##
## LEF for PtnCells ;
## created by Innovus v15.23-s045_1 on Sun Mar 23 12:35:52 2025
##

VERSION 5.8 ;

BUSBITCHARS "[]" ;
DIVIDERCHAR "/" ;

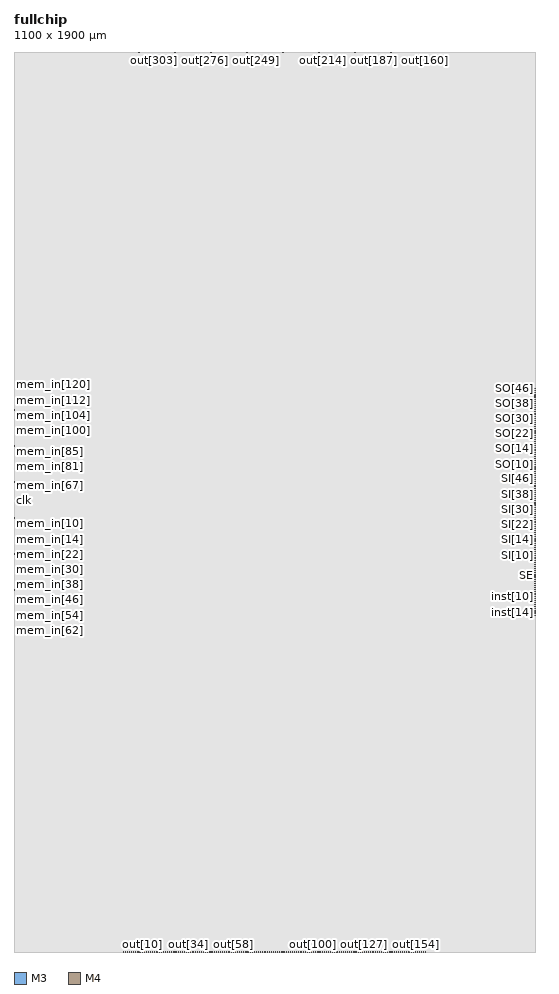
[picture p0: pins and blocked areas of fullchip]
MACRO fullchip
  CLASS BLOCK ;
  SIZE 1100.0000 BY 1900.0000 ;
  FOREIGN fullchip 0.0000 0.0000 ;
  ORIGIN 0 0 ;
  SYMMETRY X Y R90 ;
  PIN clk
    DIRECTION INPUT ;
    USE SIGNAL ;
    PORT
      LAYER M3 ;
        RECT 0.0000 952.1500 0.5200 952.2500 ;
    END
  END clk
  PIN mem_in[127]
    DIRECTION INPUT ;
    USE SIGNAL ;
    PORT
      LAYER M3 ;
        RECT 0.0000 1208.1500 0.5200 1208.2500 ;
    END
  END mem_in[127]
  PIN mem_in[126]
    DIRECTION INPUT ;
    USE SIGNAL ;
    PORT
      LAYER M3 ;
        RECT 0.0000 1204.1500 0.5200 1204.2500 ;
    END
  END mem_in[126]
  PIN mem_in[125]
    DIRECTION INPUT ;
    USE SIGNAL ;
    PORT
      LAYER M3 ;
        RECT 0.0000 1200.1500 0.5200 1200.2500 ;
    END
  END mem_in[125]
  PIN mem_in[124]
    DIRECTION INPUT ;
    USE SIGNAL ;
    PORT
      LAYER M3 ;
        RECT 0.0000 1196.1500 0.5200 1196.2500 ;
    END
  END mem_in[124]
  PIN mem_in[123]
    DIRECTION INPUT ;
    USE SIGNAL ;
    PORT
      LAYER M3 ;
        RECT 0.0000 1192.1500 0.5200 1192.2500 ;
    END
  END mem_in[123]
  PIN mem_in[122]
    DIRECTION INPUT ;
    USE SIGNAL ;
    PORT
      LAYER M3 ;
        RECT 0.0000 1188.1500 0.5200 1188.2500 ;
    END
  END mem_in[122]
  PIN mem_in[121]
    DIRECTION INPUT ;
    USE SIGNAL ;
    PORT
      LAYER M3 ;
        RECT 0.0000 1184.1500 0.5200 1184.2500 ;
    END
  END mem_in[121]
  PIN mem_in[120]
    DIRECTION INPUT ;
    USE SIGNAL ;
    PORT
      LAYER M3 ;
        RECT 0.0000 1180.1500 0.5200 1180.2500 ;
    END
  END mem_in[120]
  PIN mem_in[119]
    DIRECTION INPUT ;
    USE SIGNAL ;
    PORT
      LAYER M3 ;
        RECT 0.0000 1176.1500 0.5200 1176.2500 ;
    END
  END mem_in[119]
  PIN mem_in[118]
    DIRECTION INPUT ;
    USE SIGNAL ;
    PORT
      LAYER M3 ;
        RECT 0.0000 1172.1500 0.5200 1172.2500 ;
    END
  END mem_in[118]
  PIN mem_in[117]
    DIRECTION INPUT ;
    USE SIGNAL ;
    PORT
      LAYER M3 ;
        RECT 0.0000 1168.1500 0.5200 1168.2500 ;
    END
  END mem_in[117]
  PIN mem_in[116]
    DIRECTION INPUT ;
    USE SIGNAL ;
    PORT
      LAYER M3 ;
        RECT 0.0000 1164.1500 0.5200 1164.2500 ;
    END
  END mem_in[116]
  PIN mem_in[115]
    DIRECTION INPUT ;
    USE SIGNAL ;
    PORT
      LAYER M3 ;
        RECT 0.0000 1160.1500 0.5200 1160.2500 ;
    END
  END mem_in[115]
  PIN mem_in[114]
    DIRECTION INPUT ;
    USE SIGNAL ;
    PORT
      LAYER M3 ;
        RECT 0.0000 1156.1500 0.5200 1156.2500 ;
    END
  END mem_in[114]
  PIN mem_in[113]
    DIRECTION INPUT ;
    USE SIGNAL ;
    PORT
      LAYER M3 ;
        RECT 0.0000 1152.1500 0.5200 1152.2500 ;
    END
  END mem_in[113]
  PIN mem_in[112]
    DIRECTION INPUT ;
    USE SIGNAL ;
    PORT
      LAYER M3 ;
        RECT 0.0000 1148.1500 0.5200 1148.2500 ;
    END
  END mem_in[112]
  PIN mem_in[111]
    DIRECTION INPUT ;
    USE SIGNAL ;
    PORT
      LAYER M3 ;
        RECT 0.0000 1144.1500 0.5200 1144.2500 ;
    END
  END mem_in[111]
  PIN mem_in[110]
    DIRECTION INPUT ;
    USE SIGNAL ;
    PORT
      LAYER M3 ;
        RECT 0.0000 1140.1500 0.5200 1140.2500 ;
    END
  END mem_in[110]
  PIN mem_in[109]
    DIRECTION INPUT ;
    USE SIGNAL ;
    PORT
      LAYER M3 ;
        RECT 0.0000 1136.1500 0.5200 1136.2500 ;
    END
  END mem_in[109]
  PIN mem_in[108]
    DIRECTION INPUT ;
    USE SIGNAL ;
    PORT
      LAYER M3 ;
        RECT 0.0000 1132.1500 0.5200 1132.2500 ;
    END
  END mem_in[108]
  PIN mem_in[107]
    DIRECTION INPUT ;
    USE SIGNAL ;
    PORT
      LAYER M3 ;
        RECT 0.0000 1128.1500 0.5200 1128.2500 ;
    END
  END mem_in[107]
  PIN mem_in[106]
    DIRECTION INPUT ;
    USE SIGNAL ;
    PORT
      LAYER M3 ;
        RECT 0.0000 1124.1500 0.5200 1124.2500 ;
    END
  END mem_in[106]
  PIN mem_in[105]
    DIRECTION INPUT ;
    USE SIGNAL ;
    PORT
      LAYER M3 ;
        RECT 0.0000 1120.1500 0.5200 1120.2500 ;
    END
  END mem_in[105]
  PIN mem_in[104]
    DIRECTION INPUT ;
    USE SIGNAL ;
    PORT
      LAYER M3 ;
        RECT 0.0000 1116.1500 0.5200 1116.2500 ;
    END
  END mem_in[104]
  PIN mem_in[103]
    DIRECTION INPUT ;
    USE SIGNAL ;
    PORT
      LAYER M3 ;
        RECT 0.0000 1112.1500 0.5200 1112.2500 ;
    END
  END mem_in[103]
  PIN mem_in[102]
    DIRECTION INPUT ;
    USE SIGNAL ;
    PORT
      LAYER M3 ;
        RECT 0.0000 1108.1500 0.5200 1108.2500 ;
    END
  END mem_in[102]
  PIN mem_in[101]
    DIRECTION INPUT ;
    USE SIGNAL ;
    PORT
      LAYER M3 ;
        RECT 0.0000 1104.1500 0.5200 1104.2500 ;
    END
  END mem_in[101]
  PIN mem_in[100]
    DIRECTION INPUT ;
    USE SIGNAL ;
    PORT
      LAYER M3 ;
        RECT 0.0000 1100.1500 0.5200 1100.2500 ;
    END
  END mem_in[100]
  PIN mem_in[99]
    DIRECTION INPUT ;
    USE SIGNAL ;
    PORT
      LAYER M3 ;
        RECT 0.0000 1096.1500 0.5200 1096.2500 ;
    END
  END mem_in[99]
  PIN mem_in[98]
    DIRECTION INPUT ;
    USE SIGNAL ;
    PORT
      LAYER M3 ;
        RECT 0.0000 1092.1500 0.5200 1092.2500 ;
    END
  END mem_in[98]
  PIN mem_in[97]
    DIRECTION INPUT ;
    USE SIGNAL ;
    PORT
      LAYER M3 ;
        RECT 0.0000 1088.1500 0.5200 1088.2500 ;
    END
  END mem_in[97]
  PIN mem_in[96]
    DIRECTION INPUT ;
    USE SIGNAL ;
    PORT
      LAYER M3 ;
        RECT 0.0000 1084.1500 0.5200 1084.2500 ;
    END
  END mem_in[96]
  PIN mem_in[95]
    DIRECTION INPUT ;
    USE SIGNAL ;
    PORT
      LAYER M3 ;
        RECT 0.0000 1080.1500 0.5200 1080.2500 ;
    END
  END mem_in[95]
  PIN mem_in[94]
    DIRECTION INPUT ;
    USE SIGNAL ;
    PORT
      LAYER M3 ;
        RECT 0.0000 1076.1500 0.5200 1076.2500 ;
    END
  END mem_in[94]
  PIN mem_in[93]
    DIRECTION INPUT ;
    USE SIGNAL ;
    PORT
      LAYER M3 ;
        RECT 0.0000 1072.1500 0.5200 1072.2500 ;
    END
  END mem_in[93]
  PIN mem_in[92]
    DIRECTION INPUT ;
    USE SIGNAL ;
    PORT
      LAYER M3 ;
        RECT 0.0000 1068.1500 0.5200 1068.2500 ;
    END
  END mem_in[92]
  PIN mem_in[91]
    DIRECTION INPUT ;
    USE SIGNAL ;
    PORT
      LAYER M3 ;
        RECT 0.0000 1064.1500 0.5200 1064.2500 ;
    END
  END mem_in[91]
  PIN mem_in[90]
    DIRECTION INPUT ;
    USE SIGNAL ;
    PORT
      LAYER M3 ;
        RECT 0.0000 1060.1500 0.5200 1060.2500 ;
    END
  END mem_in[90]
  PIN mem_in[89]
    DIRECTION INPUT ;
    USE SIGNAL ;
    PORT
      LAYER M3 ;
        RECT 0.0000 1056.1500 0.5200 1056.2500 ;
    END
  END mem_in[89]
  PIN mem_in[88]
    DIRECTION INPUT ;
    USE SIGNAL ;
    PORT
      LAYER M3 ;
        RECT 0.0000 1052.1500 0.5200 1052.2500 ;
    END
  END mem_in[88]
  PIN mem_in[87]
    DIRECTION INPUT ;
    USE SIGNAL ;
    PORT
      LAYER M3 ;
        RECT 0.0000 1048.1500 0.5200 1048.2500 ;
    END
  END mem_in[87]
  PIN mem_in[86]
    DIRECTION INPUT ;
    USE SIGNAL ;
    PORT
      LAYER M3 ;
        RECT 0.0000 1044.1500 0.5200 1044.2500 ;
    END
  END mem_in[86]
  PIN mem_in[85]
    DIRECTION INPUT ;
    USE SIGNAL ;
    PORT
      LAYER M3 ;
        RECT 0.0000 1040.1500 0.5200 1040.2500 ;
    END
  END mem_in[85]
  PIN mem_in[84]
    DIRECTION INPUT ;
    USE SIGNAL ;
    PORT
      LAYER M3 ;
        RECT 0.0000 1036.1500 0.5200 1036.2500 ;
    END
  END mem_in[84]
  PIN mem_in[83]
    DIRECTION INPUT ;
    USE SIGNAL ;
    PORT
      LAYER M3 ;
        RECT 0.0000 1032.1500 0.5200 1032.2500 ;
    END
  END mem_in[83]
  PIN mem_in[82]
    DIRECTION INPUT ;
    USE SIGNAL ;
    PORT
      LAYER M3 ;
        RECT 0.0000 1028.1500 0.5200 1028.2500 ;
    END
  END mem_in[82]
  PIN mem_in[81]
    DIRECTION INPUT ;
    USE SIGNAL ;
    PORT
      LAYER M3 ;
        RECT 0.0000 1024.1500 0.5200 1024.2500 ;
    END
  END mem_in[81]
  PIN mem_in[80]
    DIRECTION INPUT ;
    USE SIGNAL ;
    PORT
      LAYER M3 ;
        RECT 0.0000 1020.1500 0.5200 1020.2500 ;
    END
  END mem_in[80]
  PIN mem_in[79]
    DIRECTION INPUT ;
    USE SIGNAL ;
    PORT
      LAYER M3 ;
        RECT 0.0000 1016.1500 0.5200 1016.2500 ;
    END
  END mem_in[79]
  PIN mem_in[78]
    DIRECTION INPUT ;
    USE SIGNAL ;
    PORT
      LAYER M3 ;
        RECT 0.0000 1012.1500 0.5200 1012.2500 ;
    END
  END mem_in[78]
  PIN mem_in[77]
    DIRECTION INPUT ;
    USE SIGNAL ;
    PORT
      LAYER M3 ;
        RECT 0.0000 1008.1500 0.5200 1008.2500 ;
    END
  END mem_in[77]
  PIN mem_in[76]
    DIRECTION INPUT ;
    USE SIGNAL ;
    PORT
      LAYER M3 ;
        RECT 0.0000 1004.1500 0.5200 1004.2500 ;
    END
  END mem_in[76]
  PIN mem_in[75]
    DIRECTION INPUT ;
    USE SIGNAL ;
    PORT
      LAYER M3 ;
        RECT 0.0000 1000.1500 0.5200 1000.2500 ;
    END
  END mem_in[75]
  PIN mem_in[74]
    DIRECTION INPUT ;
    USE SIGNAL ;
    PORT
      LAYER M3 ;
        RECT 0.0000 996.1500 0.5200 996.2500 ;
    END
  END mem_in[74]
  PIN mem_in[73]
    DIRECTION INPUT ;
    USE SIGNAL ;
    PORT
      LAYER M3 ;
        RECT 0.0000 992.1500 0.5200 992.2500 ;
    END
  END mem_in[73]
  PIN mem_in[72]
    DIRECTION INPUT ;
    USE SIGNAL ;
    PORT
      LAYER M3 ;
        RECT 0.0000 988.1500 0.5200 988.2500 ;
    END
  END mem_in[72]
  PIN mem_in[71]
    DIRECTION INPUT ;
    USE SIGNAL ;
    PORT
      LAYER M3 ;
        RECT 0.0000 984.1500 0.5200 984.2500 ;
    END
  END mem_in[71]
  PIN mem_in[70]
    DIRECTION INPUT ;
    USE SIGNAL ;
    PORT
      LAYER M3 ;
        RECT 0.0000 980.1500 0.5200 980.2500 ;
    END
  END mem_in[70]
  PIN mem_in[69]
    DIRECTION INPUT ;
    USE SIGNAL ;
    PORT
      LAYER M3 ;
        RECT 0.0000 976.1500 0.5200 976.2500 ;
    END
  END mem_in[69]
  PIN mem_in[68]
    DIRECTION INPUT ;
    USE SIGNAL ;
    PORT
      LAYER M3 ;
        RECT 0.0000 972.1500 0.5200 972.2500 ;
    END
  END mem_in[68]
  PIN mem_in[67]
    DIRECTION INPUT ;
    USE SIGNAL ;
    PORT
      LAYER M3 ;
        RECT 0.0000 968.1500 0.5200 968.2500 ;
    END
  END mem_in[67]
  PIN mem_in[66]
    DIRECTION INPUT ;
    USE SIGNAL ;
    PORT
      LAYER M3 ;
        RECT 0.0000 964.1500 0.5200 964.2500 ;
    END
  END mem_in[66]
  PIN mem_in[65]
    DIRECTION INPUT ;
    USE SIGNAL ;
    PORT
      LAYER M3 ;
        RECT 0.0000 960.1500 0.5200 960.2500 ;
    END
  END mem_in[65]
  PIN mem_in[64]
    DIRECTION INPUT ;
    USE SIGNAL ;
    PORT
      LAYER M3 ;
        RECT 0.0000 956.1500 0.5200 956.2500 ;
    END
  END mem_in[64]
  PIN mem_in[63]
    DIRECTION INPUT ;
    USE SIGNAL ;
    PORT
      LAYER M3 ;
        RECT 0.0000 692.1500 0.5200 692.2500 ;
    END
  END mem_in[63]
  PIN mem_in[62]
    DIRECTION INPUT ;
    USE SIGNAL ;
    PORT
      LAYER M3 ;
        RECT 0.0000 696.1500 0.5200 696.2500 ;
    END
  END mem_in[62]
  PIN mem_in[61]
    DIRECTION INPUT ;
    USE SIGNAL ;
    PORT
      LAYER M3 ;
        RECT 0.0000 700.1500 0.5200 700.2500 ;
    END
  END mem_in[61]
  PIN mem_in[60]
    DIRECTION INPUT ;
    USE SIGNAL ;
    PORT
      LAYER M3 ;
        RECT 0.0000 704.1500 0.5200 704.2500 ;
    END
  END mem_in[60]
  PIN mem_in[59]
    DIRECTION INPUT ;
    USE SIGNAL ;
    PORT
      LAYER M3 ;
        RECT 0.0000 708.1500 0.5200 708.2500 ;
    END
  END mem_in[59]
  PIN mem_in[58]
    DIRECTION INPUT ;
    USE SIGNAL ;
    PORT
      LAYER M3 ;
        RECT 0.0000 712.1500 0.5200 712.2500 ;
    END
  END mem_in[58]
  PIN mem_in[57]
    DIRECTION INPUT ;
    USE SIGNAL ;
    PORT
      LAYER M3 ;
        RECT 0.0000 716.1500 0.5200 716.2500 ;
    END
  END mem_in[57]
  PIN mem_in[56]
    DIRECTION INPUT ;
    USE SIGNAL ;
    PORT
      LAYER M3 ;
        RECT 0.0000 720.1500 0.5200 720.2500 ;
    END
  END mem_in[56]
  PIN mem_in[55]
    DIRECTION INPUT ;
    USE SIGNAL ;
    PORT
      LAYER M3 ;
        RECT 0.0000 724.1500 0.5200 724.2500 ;
    END
  END mem_in[55]
  PIN mem_in[54]
    DIRECTION INPUT ;
    USE SIGNAL ;
    PORT
      LAYER M3 ;
        RECT 0.0000 728.1500 0.5200 728.2500 ;
    END
  END mem_in[54]
  PIN mem_in[53]
    DIRECTION INPUT ;
    USE SIGNAL ;
    PORT
      LAYER M3 ;
        RECT 0.0000 732.1500 0.5200 732.2500 ;
    END
  END mem_in[53]
  PIN mem_in[52]
    DIRECTION INPUT ;
    USE SIGNAL ;
    PORT
      LAYER M3 ;
        RECT 0.0000 736.1500 0.5200 736.2500 ;
    END
  END mem_in[52]
  PIN mem_in[51]
    DIRECTION INPUT ;
    USE SIGNAL ;
    PORT
      LAYER M3 ;
        RECT 0.0000 740.1500 0.5200 740.2500 ;
    END
  END mem_in[51]
  PIN mem_in[50]
    DIRECTION INPUT ;
    USE SIGNAL ;
    PORT
      LAYER M3 ;
        RECT 0.0000 744.1500 0.5200 744.2500 ;
    END
  END mem_in[50]
  PIN mem_in[49]
    DIRECTION INPUT ;
    USE SIGNAL ;
    PORT
      LAYER M3 ;
        RECT 0.0000 748.1500 0.5200 748.2500 ;
    END
  END mem_in[49]
  PIN mem_in[48]
    DIRECTION INPUT ;
    USE SIGNAL ;
    PORT
      LAYER M3 ;
        RECT 0.0000 752.1500 0.5200 752.2500 ;
    END
  END mem_in[48]
  PIN mem_in[47]
    DIRECTION INPUT ;
    USE SIGNAL ;
    PORT
      LAYER M3 ;
        RECT 0.0000 756.1500 0.5200 756.2500 ;
    END
  END mem_in[47]
  PIN mem_in[46]
    DIRECTION INPUT ;
    USE SIGNAL ;
    PORT
      LAYER M3 ;
        RECT 0.0000 760.1500 0.5200 760.2500 ;
    END
  END mem_in[46]
  PIN mem_in[45]
    DIRECTION INPUT ;
    USE SIGNAL ;
    PORT
      LAYER M3 ;
        RECT 0.0000 764.1500 0.5200 764.2500 ;
    END
  END mem_in[45]
  PIN mem_in[44]
    DIRECTION INPUT ;
    USE SIGNAL ;
    PORT
      LAYER M3 ;
        RECT 0.0000 768.1500 0.5200 768.2500 ;
    END
  END mem_in[44]
  PIN mem_in[43]
    DIRECTION INPUT ;
    USE SIGNAL ;
    PORT
      LAYER M3 ;
        RECT 0.0000 772.1500 0.5200 772.2500 ;
    END
  END mem_in[43]
  PIN mem_in[42]
    DIRECTION INPUT ;
    USE SIGNAL ;
    PORT
      LAYER M3 ;
        RECT 0.0000 776.1500 0.5200 776.2500 ;
    END
  END mem_in[42]
  PIN mem_in[41]
    DIRECTION INPUT ;
    USE SIGNAL ;
    PORT
      LAYER M3 ;
        RECT 0.0000 780.1500 0.5200 780.2500 ;
    END
  END mem_in[41]
  PIN mem_in[40]
    DIRECTION INPUT ;
    USE SIGNAL ;
    PORT
      LAYER M3 ;
        RECT 0.0000 784.1500 0.5200 784.2500 ;
    END
  END mem_in[40]
  PIN mem_in[39]
    DIRECTION INPUT ;
    USE SIGNAL ;
    PORT
      LAYER M3 ;
        RECT 0.0000 788.1500 0.5200 788.2500 ;
    END
  END mem_in[39]
  PIN mem_in[38]
    DIRECTION INPUT ;
    USE SIGNAL ;
    PORT
      LAYER M3 ;
        RECT 0.0000 792.1500 0.5200 792.2500 ;
    END
  END mem_in[38]
  PIN mem_in[37]
    DIRECTION INPUT ;
    USE SIGNAL ;
    PORT
      LAYER M3 ;
        RECT 0.0000 796.1500 0.5200 796.2500 ;
    END
  END mem_in[37]
  PIN mem_in[36]
    DIRECTION INPUT ;
    USE SIGNAL ;
    PORT
      LAYER M3 ;
        RECT 0.0000 800.1500 0.5200 800.2500 ;
    END
  END mem_in[36]
  PIN mem_in[35]
    DIRECTION INPUT ;
    USE SIGNAL ;
    PORT
      LAYER M3 ;
        RECT 0.0000 804.1500 0.5200 804.2500 ;
    END
  END mem_in[35]
  PIN mem_in[34]
    DIRECTION INPUT ;
    USE SIGNAL ;
    PORT
      LAYER M3 ;
        RECT 0.0000 808.1500 0.5200 808.2500 ;
    END
  END mem_in[34]
  PIN mem_in[33]
    DIRECTION INPUT ;
    USE SIGNAL ;
    PORT
      LAYER M3 ;
        RECT 0.0000 812.1500 0.5200 812.2500 ;
    END
  END mem_in[33]
  PIN mem_in[32]
    DIRECTION INPUT ;
    USE SIGNAL ;
    PORT
      LAYER M3 ;
        RECT 0.0000 816.1500 0.5200 816.2500 ;
    END
  END mem_in[32]
  PIN mem_in[31]
    DIRECTION INPUT ;
    USE SIGNAL ;
    PORT
      LAYER M3 ;
        RECT 0.0000 820.1500 0.5200 820.2500 ;
    END
  END mem_in[31]
  PIN mem_in[30]
    DIRECTION INPUT ;
    USE SIGNAL ;
    PORT
      LAYER M3 ;
        RECT 0.0000 824.1500 0.5200 824.2500 ;
    END
  END mem_in[30]
  PIN mem_in[29]
    DIRECTION INPUT ;
    USE SIGNAL ;
    PORT
      LAYER M3 ;
        RECT 0.0000 828.1500 0.5200 828.2500 ;
    END
  END mem_in[29]
  PIN mem_in[28]
    DIRECTION INPUT ;
    USE SIGNAL ;
    PORT
      LAYER M3 ;
        RECT 0.0000 832.1500 0.5200 832.2500 ;
    END
  END mem_in[28]
  PIN mem_in[27]
    DIRECTION INPUT ;
    USE SIGNAL ;
    PORT
      LAYER M3 ;
        RECT 0.0000 836.1500 0.5200 836.2500 ;
    END
  END mem_in[27]
  PIN mem_in[26]
    DIRECTION INPUT ;
    USE SIGNAL ;
    PORT
      LAYER M3 ;
        RECT 0.0000 840.1500 0.5200 840.2500 ;
    END
  END mem_in[26]
  PIN mem_in[25]
    DIRECTION INPUT ;
    USE SIGNAL ;
    PORT
      LAYER M3 ;
        RECT 0.0000 844.1500 0.5200 844.2500 ;
    END
  END mem_in[25]
  PIN mem_in[24]
    DIRECTION INPUT ;
    USE SIGNAL ;
    PORT
      LAYER M3 ;
        RECT 0.0000 848.1500 0.5200 848.2500 ;
    END
  END mem_in[24]
  PIN mem_in[23]
    DIRECTION INPUT ;
    USE SIGNAL ;
    PORT
      LAYER M3 ;
        RECT 0.0000 852.1500 0.5200 852.2500 ;
    END
  END mem_in[23]
  PIN mem_in[22]
    DIRECTION INPUT ;
    USE SIGNAL ;
    PORT
      LAYER M3 ;
        RECT 0.0000 856.1500 0.5200 856.2500 ;
    END
  END mem_in[22]
  PIN mem_in[21]
    DIRECTION INPUT ;
    USE SIGNAL ;
    PORT
      LAYER M3 ;
        RECT 0.0000 860.1500 0.5200 860.2500 ;
    END
  END mem_in[21]
  PIN mem_in[20]
    DIRECTION INPUT ;
    USE SIGNAL ;
    PORT
      LAYER M3 ;
        RECT 0.0000 864.1500 0.5200 864.2500 ;
    END
  END mem_in[20]
  PIN mem_in[19]
    DIRECTION INPUT ;
    USE SIGNAL ;
    PORT
      LAYER M3 ;
        RECT 0.0000 868.1500 0.5200 868.2500 ;
    END
  END mem_in[19]
  PIN mem_in[18]
    DIRECTION INPUT ;
    USE SIGNAL ;
    PORT
      LAYER M3 ;
        RECT 0.0000 872.1500 0.5200 872.2500 ;
    END
  END mem_in[18]
  PIN mem_in[17]
    DIRECTION INPUT ;
    USE SIGNAL ;
    PORT
      LAYER M3 ;
        RECT 0.0000 876.1500 0.5200 876.2500 ;
    END
  END mem_in[17]
  PIN mem_in[16]
    DIRECTION INPUT ;
    USE SIGNAL ;
    PORT
      LAYER M3 ;
        RECT 0.0000 880.1500 0.5200 880.2500 ;
    END
  END mem_in[16]
  PIN mem_in[15]
    DIRECTION INPUT ;
    USE SIGNAL ;
    PORT
      LAYER M3 ;
        RECT 0.0000 884.1500 0.5200 884.2500 ;
    END
  END mem_in[15]
  PIN mem_in[14]
    DIRECTION INPUT ;
    USE SIGNAL ;
    PORT
      LAYER M3 ;
        RECT 0.0000 888.1500 0.5200 888.2500 ;
    END
  END mem_in[14]
  PIN mem_in[13]
    DIRECTION INPUT ;
    USE SIGNAL ;
    PORT
      LAYER M3 ;
        RECT 0.0000 892.1500 0.5200 892.2500 ;
    END
  END mem_in[13]
  PIN mem_in[12]
    DIRECTION INPUT ;
    USE SIGNAL ;
    PORT
      LAYER M3 ;
        RECT 0.0000 896.1500 0.5200 896.2500 ;
    END
  END mem_in[12]
  PIN mem_in[11]
    DIRECTION INPUT ;
    USE SIGNAL ;
    PORT
      LAYER M3 ;
        RECT 0.0000 900.1500 0.5200 900.2500 ;
    END
  END mem_in[11]
  PIN mem_in[10]
    DIRECTION INPUT ;
    USE SIGNAL ;
    PORT
      LAYER M3 ;
        RECT 0.0000 904.1500 0.5200 904.2500 ;
    END
  END mem_in[10]
  PIN mem_in[9]
    DIRECTION INPUT ;
    USE SIGNAL ;
    PORT
      LAYER M3 ;
        RECT 0.0000 908.1500 0.5200 908.2500 ;
    END
  END mem_in[9]
  PIN mem_in[8]
    DIRECTION INPUT ;
    USE SIGNAL ;
    PORT
      LAYER M3 ;
        RECT 0.0000 912.1500 0.5200 912.2500 ;
    END
  END mem_in[8]
  PIN mem_in[7]
    DIRECTION INPUT ;
    USE SIGNAL ;
    PORT
      LAYER M3 ;
        RECT 0.0000 916.1500 0.5200 916.2500 ;
    END
  END mem_in[7]
  PIN mem_in[6]
    DIRECTION INPUT ;
    USE SIGNAL ;
    PORT
      LAYER M3 ;
        RECT 0.0000 920.1500 0.5200 920.2500 ;
    END
  END mem_in[6]
  PIN mem_in[5]
    DIRECTION INPUT ;
    USE SIGNAL ;
    PORT
      LAYER M3 ;
        RECT 0.0000 924.1500 0.5200 924.2500 ;
    END
  END mem_in[5]
  PIN mem_in[4]
    DIRECTION INPUT ;
    USE SIGNAL ;
    PORT
      LAYER M3 ;
        RECT 0.0000 928.1500 0.5200 928.2500 ;
    END
  END mem_in[4]
  PIN mem_in[3]
    DIRECTION INPUT ;
    USE SIGNAL ;
    PORT
      LAYER M3 ;
        RECT 0.0000 932.1500 0.5200 932.2500 ;
    END
  END mem_in[3]
  PIN mem_in[2]
    DIRECTION INPUT ;
    USE SIGNAL ;
    PORT
      LAYER M3 ;
        RECT 0.0000 936.1500 0.5200 936.2500 ;
    END
  END mem_in[2]
  PIN mem_in[1]
    DIRECTION INPUT ;
    USE SIGNAL ;
    PORT
      LAYER M3 ;
        RECT 0.0000 940.1500 0.5200 940.2500 ;
    END
  END mem_in[1]
  PIN mem_in[0]
    DIRECTION INPUT ;
    USE SIGNAL ;
    PORT
      LAYER M3 ;
        RECT 0.0000 944.1500 0.5200 944.2500 ;
    END
  END mem_in[0]
  PIN inst[20]
    DIRECTION INPUT ;
    USE SIGNAL ;
    PORT
      LAYER M3 ;
        RECT 1099.4800 709.7500 1100.0000 709.8500 ;
    END
  END inst[20]
  PIN inst[19]
    DIRECTION INPUT ;
    USE SIGNAL ;
    PORT
      LAYER M3 ;
        RECT 1099.4800 713.7500 1100.0000 713.8500 ;
    END
  END inst[19]
  PIN inst[18]
    DIRECTION INPUT ;
    USE SIGNAL ;
    PORT
      LAYER M3 ;
        RECT 1099.4800 717.7500 1100.0000 717.8500 ;
    END
  END inst[18]
  PIN inst[17]
    DIRECTION INPUT ;
    USE SIGNAL ;
    PORT
      LAYER M3 ;
        RECT 1099.4800 721.7500 1100.0000 721.8500 ;
    END
  END inst[17]
  PIN inst[16]
    DIRECTION INPUT ;
    USE SIGNAL ;
    PORT
      LAYER M3 ;
        RECT 1099.4800 725.7500 1100.0000 725.8500 ;
    END
  END inst[16]
  PIN inst[15]
    DIRECTION INPUT ;
    USE SIGNAL ;
    PORT
      LAYER M3 ;
        RECT 1099.4800 729.7500 1100.0000 729.8500 ;
    END
  END inst[15]
  PIN inst[14]
    DIRECTION INPUT ;
    USE SIGNAL ;
    PORT
      LAYER M3 ;
        RECT 1099.4800 733.7500 1100.0000 733.8500 ;
    END
  END inst[14]
  PIN inst[13]
    DIRECTION INPUT ;
    USE SIGNAL ;
    PORT
      LAYER M3 ;
        RECT 1099.4800 737.7500 1100.0000 737.8500 ;
    END
  END inst[13]
  PIN inst[12]
    DIRECTION INPUT ;
    USE SIGNAL ;
    PORT
      LAYER M3 ;
        RECT 1099.4800 741.7500 1100.0000 741.8500 ;
    END
  END inst[12]
  PIN inst[11]
    DIRECTION INPUT ;
    USE SIGNAL ;
    PORT
      LAYER M3 ;
        RECT 1099.4800 745.7500 1100.0000 745.8500 ;
    END
  END inst[11]
  PIN inst[10]
    DIRECTION INPUT ;
    USE SIGNAL ;
    PORT
      LAYER M3 ;
        RECT 1099.4800 749.7500 1100.0000 749.8500 ;
    END
  END inst[10]
  PIN inst[9]
    DIRECTION INPUT ;
    USE SIGNAL ;
    PORT
      LAYER M3 ;
        RECT 1099.4800 753.7500 1100.0000 753.8500 ;
    END
  END inst[9]
  PIN inst[8]
    DIRECTION INPUT ;
    USE SIGNAL ;
    PORT
      LAYER M3 ;
        RECT 1099.4800 757.7500 1100.0000 757.8500 ;
    END
  END inst[8]
  PIN inst[7]
    DIRECTION INPUT ;
    USE SIGNAL ;
    PORT
      LAYER M3 ;
        RECT 1099.4800 761.7500 1100.0000 761.8500 ;
    END
  END inst[7]
  PIN inst[6]
    DIRECTION INPUT ;
    USE SIGNAL ;
    PORT
      LAYER M3 ;
        RECT 1099.4800 765.7500 1100.0000 765.8500 ;
    END
  END inst[6]
  PIN inst[5]
    DIRECTION INPUT ;
    USE SIGNAL ;
    PORT
      LAYER M3 ;
        RECT 1099.4800 769.7500 1100.0000 769.8500 ;
    END
  END inst[5]
  PIN inst[4]
    DIRECTION INPUT ;
    USE SIGNAL ;
    PORT
      LAYER M3 ;
        RECT 1099.4800 773.7500 1100.0000 773.8500 ;
    END
  END inst[4]
  PIN inst[3]
    DIRECTION INPUT ;
    USE SIGNAL ;
    PORT
      LAYER M3 ;
        RECT 1099.4800 777.7500 1100.0000 777.8500 ;
    END
  END inst[3]
  PIN inst[2]
    DIRECTION INPUT ;
    USE SIGNAL ;
    PORT
      LAYER M3 ;
        RECT 1099.4800 781.7500 1100.0000 781.8500 ;
    END
  END inst[2]
  PIN inst[1]
    DIRECTION INPUT ;
    USE SIGNAL ;
    PORT
      LAYER M3 ;
        RECT 1099.4800 785.7500 1100.0000 785.8500 ;
    END
  END inst[1]
  PIN inst[0]
    DIRECTION INPUT ;
    USE SIGNAL ;
    PORT
      LAYER M3 ;
        RECT 1099.4800 789.7500 1100.0000 789.8500 ;
    END
  END inst[0]
  PIN reset
    DIRECTION INPUT ;
    USE SIGNAL ;
    PORT
      LAYER M3 ;
        RECT 0.0000 948.1500 0.5200 948.2500 ;
    END
  END reset
  PIN out[319]
    DIRECTION OUTPUT ;
    USE SIGNAL ;
    PORT
      LAYER M4 ;
        RECT 231.8500 1899.4800 231.9500 1900.0000 ;
    END
  END out[319]
  PIN out[318]
    DIRECTION OUTPUT ;
    USE SIGNAL ;
    PORT
      LAYER M4 ;
        RECT 235.8500 1899.4800 235.9500 1900.0000 ;
    END
  END out[318]
  PIN out[317]
    DIRECTION OUTPUT ;
    USE SIGNAL ;
    PORT
      LAYER M4 ;
        RECT 239.8500 1899.4800 239.9500 1900.0000 ;
    END
  END out[317]
  PIN out[316]
    DIRECTION OUTPUT ;
    USE SIGNAL ;
    PORT
      LAYER M4 ;
        RECT 243.8500 1899.4800 243.9500 1900.0000 ;
    END
  END out[316]
  PIN out[315]
    DIRECTION OUTPUT ;
    USE SIGNAL ;
    PORT
      LAYER M4 ;
        RECT 247.8500 1899.4800 247.9500 1900.0000 ;
    END
  END out[315]
  PIN out[314]
    DIRECTION OUTPUT ;
    USE SIGNAL ;
    PORT
      LAYER M4 ;
        RECT 251.8500 1899.4800 251.9500 1900.0000 ;
    END
  END out[314]
  PIN out[313]
    DIRECTION OUTPUT ;
    USE SIGNAL ;
    PORT
      LAYER M4 ;
        RECT 255.8500 1899.4800 255.9500 1900.0000 ;
    END
  END out[313]
  PIN out[312]
    DIRECTION OUTPUT ;
    USE SIGNAL ;
    PORT
      LAYER M4 ;
        RECT 259.8500 1899.4800 259.9500 1900.0000 ;
    END
  END out[312]
  PIN out[311]
    DIRECTION OUTPUT ;
    USE SIGNAL ;
    PORT
      LAYER M4 ;
        RECT 263.8500 1899.4800 263.9500 1900.0000 ;
    END
  END out[311]
  PIN out[310]
    DIRECTION OUTPUT ;
    USE SIGNAL ;
    PORT
      LAYER M4 ;
        RECT 267.8500 1899.4800 267.9500 1900.0000 ;
    END
  END out[310]
  PIN out[309]
    DIRECTION OUTPUT ;
    USE SIGNAL ;
    PORT
      LAYER M4 ;
        RECT 271.8500 1899.4800 271.9500 1900.0000 ;
    END
  END out[309]
  PIN out[308]
    DIRECTION OUTPUT ;
    USE SIGNAL ;
    PORT
      LAYER M4 ;
        RECT 275.8500 1899.4800 275.9500 1900.0000 ;
    END
  END out[308]
  PIN out[307]
    DIRECTION OUTPUT ;
    USE SIGNAL ;
    PORT
      LAYER M4 ;
        RECT 279.8500 1899.4800 279.9500 1900.0000 ;
    END
  END out[307]
  PIN out[306]
    DIRECTION OUTPUT ;
    USE SIGNAL ;
    PORT
      LAYER M4 ;
        RECT 283.8500 1899.4800 283.9500 1900.0000 ;
    END
  END out[306]
  PIN out[305]
    DIRECTION OUTPUT ;
    USE SIGNAL ;
    PORT
      LAYER M4 ;
        RECT 287.8500 1899.4800 287.9500 1900.0000 ;
    END
  END out[305]
  PIN out[304]
    DIRECTION OUTPUT ;
    USE SIGNAL ;
    PORT
      LAYER M4 ;
        RECT 291.8500 1899.4800 291.9500 1900.0000 ;
    END
  END out[304]
  PIN out[303]
    DIRECTION OUTPUT ;
    USE SIGNAL ;
    PORT
      LAYER M4 ;
        RECT 295.8500 1899.4800 295.9500 1900.0000 ;
    END
  END out[303]
  PIN out[302]
    DIRECTION OUTPUT ;
    USE SIGNAL ;
    PORT
      LAYER M4 ;
        RECT 299.8500 1899.4800 299.9500 1900.0000 ;
    END
  END out[302]
  PIN out[301]
    DIRECTION OUTPUT ;
    USE SIGNAL ;
    PORT
      LAYER M4 ;
        RECT 303.8500 1899.4800 303.9500 1900.0000 ;
    END
  END out[301]
  PIN out[300]
    DIRECTION OUTPUT ;
    USE SIGNAL ;
    PORT
      LAYER M4 ;
        RECT 307.8500 1899.4800 307.9500 1900.0000 ;
    END
  END out[300]
  PIN out[299]
    DIRECTION OUTPUT ;
    USE SIGNAL ;
    PORT
      LAYER M4 ;
        RECT 311.8500 1899.4800 311.9500 1900.0000 ;
    END
  END out[299]
  PIN out[298]
    DIRECTION OUTPUT ;
    USE SIGNAL ;
    PORT
      LAYER M4 ;
        RECT 315.8500 1899.4800 315.9500 1900.0000 ;
    END
  END out[298]
  PIN out[297]
    DIRECTION OUTPUT ;
    USE SIGNAL ;
    PORT
      LAYER M4 ;
        RECT 319.8500 1899.4800 319.9500 1900.0000 ;
    END
  END out[297]
  PIN out[296]
    DIRECTION OUTPUT ;
    USE SIGNAL ;
    PORT
      LAYER M4 ;
        RECT 323.8500 1899.4800 323.9500 1900.0000 ;
    END
  END out[296]
  PIN out[295]
    DIRECTION OUTPUT ;
    USE SIGNAL ;
    PORT
      LAYER M4 ;
        RECT 327.8500 1899.4800 327.9500 1900.0000 ;
    END
  END out[295]
  PIN out[294]
    DIRECTION OUTPUT ;
    USE SIGNAL ;
    PORT
      LAYER M4 ;
        RECT 331.8500 1899.4800 331.9500 1900.0000 ;
    END
  END out[294]
  PIN out[293]
    DIRECTION OUTPUT ;
    USE SIGNAL ;
    PORT
      LAYER M4 ;
        RECT 335.8500 1899.4800 335.9500 1900.0000 ;
    END
  END out[293]
  PIN out[292]
    DIRECTION OUTPUT ;
    USE SIGNAL ;
    PORT
      LAYER M4 ;
        RECT 339.8500 1899.4800 339.9500 1900.0000 ;
    END
  END out[292]
  PIN out[291]
    DIRECTION OUTPUT ;
    USE SIGNAL ;
    PORT
      LAYER M4 ;
        RECT 343.8500 1899.4800 343.9500 1900.0000 ;
    END
  END out[291]
  PIN out[290]
    DIRECTION OUTPUT ;
    USE SIGNAL ;
    PORT
      LAYER M4 ;
        RECT 347.8500 1899.4800 347.9500 1900.0000 ;
    END
  END out[290]
  PIN out[289]
    DIRECTION OUTPUT ;
    USE SIGNAL ;
    PORT
      LAYER M4 ;
        RECT 351.8500 1899.4800 351.9500 1900.0000 ;
    END
  END out[289]
  PIN out[288]
    DIRECTION OUTPUT ;
    USE SIGNAL ;
    PORT
      LAYER M4 ;
        RECT 355.8500 1899.4800 355.9500 1900.0000 ;
    END
  END out[288]
  PIN out[287]
    DIRECTION OUTPUT ;
    USE SIGNAL ;
    PORT
      LAYER M4 ;
        RECT 359.8500 1899.4800 359.9500 1900.0000 ;
    END
  END out[287]
  PIN out[286]
    DIRECTION OUTPUT ;
    USE SIGNAL ;
    PORT
      LAYER M4 ;
        RECT 363.8500 1899.4800 363.9500 1900.0000 ;
    END
  END out[286]
  PIN out[285]
    DIRECTION OUTPUT ;
    USE SIGNAL ;
    PORT
      LAYER M4 ;
        RECT 367.8500 1899.4800 367.9500 1900.0000 ;
    END
  END out[285]
  PIN out[284]
    DIRECTION OUTPUT ;
    USE SIGNAL ;
    PORT
      LAYER M4 ;
        RECT 371.8500 1899.4800 371.9500 1900.0000 ;
    END
  END out[284]
  PIN out[283]
    DIRECTION OUTPUT ;
    USE SIGNAL ;
    PORT
      LAYER M4 ;
        RECT 375.8500 1899.4800 375.9500 1900.0000 ;
    END
  END out[283]
  PIN out[282]
    DIRECTION OUTPUT ;
    USE SIGNAL ;
    PORT
      LAYER M4 ;
        RECT 379.8500 1899.4800 379.9500 1900.0000 ;
    END
  END out[282]
  PIN out[281]
    DIRECTION OUTPUT ;
    USE SIGNAL ;
    PORT
      LAYER M4 ;
        RECT 383.8500 1899.4800 383.9500 1900.0000 ;
    END
  END out[281]
  PIN out[280]
    DIRECTION OUTPUT ;
    USE SIGNAL ;
    PORT
      LAYER M4 ;
        RECT 387.8500 1899.4800 387.9500 1900.0000 ;
    END
  END out[280]
  PIN out[279]
    DIRECTION OUTPUT ;
    USE SIGNAL ;
    PORT
      LAYER M4 ;
        RECT 391.8500 1899.4800 391.9500 1900.0000 ;
    END
  END out[279]
  PIN out[278]
    DIRECTION OUTPUT ;
    USE SIGNAL ;
    PORT
      LAYER M4 ;
        RECT 395.8500 1899.4800 395.9500 1900.0000 ;
    END
  END out[278]
  PIN out[277]
    DIRECTION OUTPUT ;
    USE SIGNAL ;
    PORT
      LAYER M4 ;
        RECT 399.8500 1899.4800 399.9500 1900.0000 ;
    END
  END out[277]
  PIN out[276]
    DIRECTION OUTPUT ;
    USE SIGNAL ;
    PORT
      LAYER M4 ;
        RECT 403.8500 1899.4800 403.9500 1900.0000 ;
    END
  END out[276]
  PIN out[275]
    DIRECTION OUTPUT ;
    USE SIGNAL ;
    PORT
      LAYER M4 ;
        RECT 407.8500 1899.4800 407.9500 1900.0000 ;
    END
  END out[275]
  PIN out[274]
    DIRECTION OUTPUT ;
    USE SIGNAL ;
    PORT
      LAYER M4 ;
        RECT 411.8500 1899.4800 411.9500 1900.0000 ;
    END
  END out[274]
  PIN out[273]
    DIRECTION OUTPUT ;
    USE SIGNAL ;
    PORT
      LAYER M4 ;
        RECT 415.8500 1899.4800 415.9500 1900.0000 ;
    END
  END out[273]
  PIN out[272]
    DIRECTION OUTPUT ;
    USE SIGNAL ;
    PORT
      LAYER M4 ;
        RECT 419.8500 1899.4800 419.9500 1900.0000 ;
    END
  END out[272]
  PIN out[271]
    DIRECTION OUTPUT ;
    USE SIGNAL ;
    PORT
      LAYER M4 ;
        RECT 423.8500 1899.4800 423.9500 1900.0000 ;
    END
  END out[271]
  PIN out[270]
    DIRECTION OUTPUT ;
    USE SIGNAL ;
    PORT
      LAYER M4 ;
        RECT 427.8500 1899.4800 427.9500 1900.0000 ;
    END
  END out[270]
  PIN out[269]
    DIRECTION OUTPUT ;
    USE SIGNAL ;
    PORT
      LAYER M4 ;
        RECT 431.8500 1899.4800 431.9500 1900.0000 ;
    END
  END out[269]
  PIN out[268]
    DIRECTION OUTPUT ;
    USE SIGNAL ;
    PORT
      LAYER M4 ;
        RECT 435.8500 1899.4800 435.9500 1900.0000 ;
    END
  END out[268]
  PIN out[267]
    DIRECTION OUTPUT ;
    USE SIGNAL ;
    PORT
      LAYER M4 ;
        RECT 439.8500 1899.4800 439.9500 1900.0000 ;
    END
  END out[267]
  PIN out[266]
    DIRECTION OUTPUT ;
    USE SIGNAL ;
    PORT
      LAYER M4 ;
        RECT 443.8500 1899.4800 443.9500 1900.0000 ;
    END
  END out[266]
  PIN out[265]
    DIRECTION OUTPUT ;
    USE SIGNAL ;
    PORT
      LAYER M4 ;
        RECT 447.8500 1899.4800 447.9500 1900.0000 ;
    END
  END out[265]
  PIN out[264]
    DIRECTION OUTPUT ;
    USE SIGNAL ;
    PORT
      LAYER M4 ;
        RECT 451.8500 1899.4800 451.9500 1900.0000 ;
    END
  END out[264]
  PIN out[263]
    DIRECTION OUTPUT ;
    USE SIGNAL ;
    PORT
      LAYER M4 ;
        RECT 455.8500 1899.4800 455.9500 1900.0000 ;
    END
  END out[263]
  PIN out[262]
    DIRECTION OUTPUT ;
    USE SIGNAL ;
    PORT
      LAYER M4 ;
        RECT 459.8500 1899.4800 459.9500 1900.0000 ;
    END
  END out[262]
  PIN out[261]
    DIRECTION OUTPUT ;
    USE SIGNAL ;
    PORT
      LAYER M4 ;
        RECT 463.8500 1899.4800 463.9500 1900.0000 ;
    END
  END out[261]
  PIN out[260]
    DIRECTION OUTPUT ;
    USE SIGNAL ;
    PORT
      LAYER M4 ;
        RECT 467.8500 1899.4800 467.9500 1900.0000 ;
    END
  END out[260]
  PIN out[259]
    DIRECTION OUTPUT ;
    USE SIGNAL ;
    PORT
      LAYER M4 ;
        RECT 471.8500 1899.4800 471.9500 1900.0000 ;
    END
  END out[259]
  PIN out[258]
    DIRECTION OUTPUT ;
    USE SIGNAL ;
    PORT
      LAYER M4 ;
        RECT 475.8500 1899.4800 475.9500 1900.0000 ;
    END
  END out[258]
  PIN out[257]
    DIRECTION OUTPUT ;
    USE SIGNAL ;
    PORT
      LAYER M4 ;
        RECT 479.8500 1899.4800 479.9500 1900.0000 ;
    END
  END out[257]
  PIN out[256]
    DIRECTION OUTPUT ;
    USE SIGNAL ;
    PORT
      LAYER M4 ;
        RECT 483.8500 1899.4800 483.9500 1900.0000 ;
    END
  END out[256]
  PIN out[255]
    DIRECTION OUTPUT ;
    USE SIGNAL ;
    PORT
      LAYER M4 ;
        RECT 487.8500 1899.4800 487.9500 1900.0000 ;
    END
  END out[255]
  PIN out[254]
    DIRECTION OUTPUT ;
    USE SIGNAL ;
    PORT
      LAYER M4 ;
        RECT 491.8500 1899.4800 491.9500 1900.0000 ;
    END
  END out[254]
  PIN out[253]
    DIRECTION OUTPUT ;
    USE SIGNAL ;
    PORT
      LAYER M4 ;
        RECT 495.8500 1899.4800 495.9500 1900.0000 ;
    END
  END out[253]
  PIN out[252]
    DIRECTION OUTPUT ;
    USE SIGNAL ;
    PORT
      LAYER M4 ;
        RECT 499.8500 1899.4800 499.9500 1900.0000 ;
    END
  END out[252]
  PIN out[251]
    DIRECTION OUTPUT ;
    USE SIGNAL ;
    PORT
      LAYER M4 ;
        RECT 503.8500 1899.4800 503.9500 1900.0000 ;
    END
  END out[251]
  PIN out[250]
    DIRECTION OUTPUT ;
    USE SIGNAL ;
    PORT
      LAYER M4 ;
        RECT 507.8500 1899.4800 507.9500 1900.0000 ;
    END
  END out[250]
  PIN out[249]
    DIRECTION OUTPUT ;
    USE SIGNAL ;
    PORT
      LAYER M4 ;
        RECT 511.8500 1899.4800 511.9500 1900.0000 ;
    END
  END out[249]
  PIN out[248]
    DIRECTION OUTPUT ;
    USE SIGNAL ;
    PORT
      LAYER M4 ;
        RECT 515.8500 1899.4800 515.9500 1900.0000 ;
    END
  END out[248]
  PIN out[247]
    DIRECTION OUTPUT ;
    USE SIGNAL ;
    PORT
      LAYER M4 ;
        RECT 519.8500 1899.4800 519.9500 1900.0000 ;
    END
  END out[247]
  PIN out[246]
    DIRECTION OUTPUT ;
    USE SIGNAL ;
    PORT
      LAYER M4 ;
        RECT 523.8500 1899.4800 523.9500 1900.0000 ;
    END
  END out[246]
  PIN out[245]
    DIRECTION OUTPUT ;
    USE SIGNAL ;
    PORT
      LAYER M4 ;
        RECT 527.8500 1899.4800 527.9500 1900.0000 ;
    END
  END out[245]
  PIN out[244]
    DIRECTION OUTPUT ;
    USE SIGNAL ;
    PORT
      LAYER M4 ;
        RECT 531.8500 1899.4800 531.9500 1900.0000 ;
    END
  END out[244]
  PIN out[243]
    DIRECTION OUTPUT ;
    USE SIGNAL ;
    PORT
      LAYER M4 ;
        RECT 535.8500 1899.4800 535.9500 1900.0000 ;
    END
  END out[243]
  PIN out[242]
    DIRECTION OUTPUT ;
    USE SIGNAL ;
    PORT
      LAYER M4 ;
        RECT 539.8500 1899.4800 539.9500 1900.0000 ;
    END
  END out[242]
  PIN out[241]
    DIRECTION OUTPUT ;
    USE SIGNAL ;
    PORT
      LAYER M4 ;
        RECT 543.8500 1899.4800 543.9500 1900.0000 ;
    END
  END out[241]
  PIN out[240]
    DIRECTION OUTPUT ;
    USE SIGNAL ;
    PORT
      LAYER M4 ;
        RECT 547.8500 1899.4800 547.9500 1900.0000 ;
    END
  END out[240]
  PIN out[239]
    DIRECTION OUTPUT ;
    USE SIGNAL ;
    PORT
      LAYER M4 ;
        RECT 551.8500 1899.4800 551.9500 1900.0000 ;
    END
  END out[239]
  PIN out[238]
    DIRECTION OUTPUT ;
    USE SIGNAL ;
    PORT
      LAYER M4 ;
        RECT 555.8500 1899.4800 555.9500 1900.0000 ;
    END
  END out[238]
  PIN out[237]
    DIRECTION OUTPUT ;
    USE SIGNAL ;
    PORT
      LAYER M4 ;
        RECT 559.8500 1899.4800 559.9500 1900.0000 ;
    END
  END out[237]
  PIN out[236]
    DIRECTION OUTPUT ;
    USE SIGNAL ;
    PORT
      LAYER M4 ;
        RECT 563.8500 1899.4800 563.9500 1900.0000 ;
    END
  END out[236]
  PIN out[235]
    DIRECTION OUTPUT ;
    USE SIGNAL ;
    PORT
      LAYER M4 ;
        RECT 567.8500 1899.4800 567.9500 1900.0000 ;
    END
  END out[235]
  PIN out[234]
    DIRECTION OUTPUT ;
    USE SIGNAL ;
    PORT
      LAYER M4 ;
        RECT 571.8500 1899.4800 571.9500 1900.0000 ;
    END
  END out[234]
  PIN out[233]
    DIRECTION OUTPUT ;
    USE SIGNAL ;
    PORT
      LAYER M4 ;
        RECT 575.8500 1899.4800 575.9500 1900.0000 ;
    END
  END out[233]
  PIN out[232]
    DIRECTION OUTPUT ;
    USE SIGNAL ;
    PORT
      LAYER M4 ;
        RECT 579.8500 1899.4800 579.9500 1900.0000 ;
    END
  END out[232]
  PIN out[231]
    DIRECTION OUTPUT ;
    USE SIGNAL ;
    PORT
      LAYER M4 ;
        RECT 583.8500 1899.4800 583.9500 1900.0000 ;
    END
  END out[231]
  PIN out[230]
    DIRECTION OUTPUT ;
    USE SIGNAL ;
    PORT
      LAYER M4 ;
        RECT 587.8500 1899.4800 587.9500 1900.0000 ;
    END
  END out[230]
  PIN out[229]
    DIRECTION OUTPUT ;
    USE SIGNAL ;
    PORT
      LAYER M4 ;
        RECT 591.8500 1899.4800 591.9500 1900.0000 ;
    END
  END out[229]
  PIN out[228]
    DIRECTION OUTPUT ;
    USE SIGNAL ;
    PORT
      LAYER M4 ;
        RECT 595.8500 1899.4800 595.9500 1900.0000 ;
    END
  END out[228]
  PIN out[227]
    DIRECTION OUTPUT ;
    USE SIGNAL ;
    PORT
      LAYER M4 ;
        RECT 599.8500 1899.4800 599.9500 1900.0000 ;
    END
  END out[227]
  PIN out[226]
    DIRECTION OUTPUT ;
    USE SIGNAL ;
    PORT
      LAYER M4 ;
        RECT 603.8500 1899.4800 603.9500 1900.0000 ;
    END
  END out[226]
  PIN out[225]
    DIRECTION OUTPUT ;
    USE SIGNAL ;
    PORT
      LAYER M4 ;
        RECT 607.8500 1899.4800 607.9500 1900.0000 ;
    END
  END out[225]
  PIN out[224]
    DIRECTION OUTPUT ;
    USE SIGNAL ;
    PORT
      LAYER M4 ;
        RECT 611.8500 1899.4800 611.9500 1900.0000 ;
    END
  END out[224]
  PIN out[223]
    DIRECTION OUTPUT ;
    USE SIGNAL ;
    PORT
      LAYER M4 ;
        RECT 615.8500 1899.4800 615.9500 1900.0000 ;
    END
  END out[223]
  PIN out[222]
    DIRECTION OUTPUT ;
    USE SIGNAL ;
    PORT
      LAYER M4 ;
        RECT 619.8500 1899.4800 619.9500 1900.0000 ;
    END
  END out[222]
  PIN out[221]
    DIRECTION OUTPUT ;
    USE SIGNAL ;
    PORT
      LAYER M4 ;
        RECT 623.8500 1899.4800 623.9500 1900.0000 ;
    END
  END out[221]
  PIN out[220]
    DIRECTION OUTPUT ;
    USE SIGNAL ;
    PORT
      LAYER M4 ;
        RECT 627.8500 1899.4800 627.9500 1900.0000 ;
    END
  END out[220]
  PIN out[219]
    DIRECTION OUTPUT ;
    USE SIGNAL ;
    PORT
      LAYER M4 ;
        RECT 631.8500 1899.4800 631.9500 1900.0000 ;
    END
  END out[219]
  PIN out[218]
    DIRECTION OUTPUT ;
    USE SIGNAL ;
    PORT
      LAYER M4 ;
        RECT 635.8500 1899.4800 635.9500 1900.0000 ;
    END
  END out[218]
  PIN out[217]
    DIRECTION OUTPUT ;
    USE SIGNAL ;
    PORT
      LAYER M4 ;
        RECT 639.8500 1899.4800 639.9500 1900.0000 ;
    END
  END out[217]
  PIN out[216]
    DIRECTION OUTPUT ;
    USE SIGNAL ;
    PORT
      LAYER M4 ;
        RECT 643.8500 1899.4800 643.9500 1900.0000 ;
    END
  END out[216]
  PIN out[215]
    DIRECTION OUTPUT ;
    USE SIGNAL ;
    PORT
      LAYER M4 ;
        RECT 647.8500 1899.4800 647.9500 1900.0000 ;
    END
  END out[215]
  PIN out[214]
    DIRECTION OUTPUT ;
    USE SIGNAL ;
    PORT
      LAYER M4 ;
        RECT 651.8500 1899.4800 651.9500 1900.0000 ;
    END
  END out[214]
  PIN out[213]
    DIRECTION OUTPUT ;
    USE SIGNAL ;
    PORT
      LAYER M4 ;
        RECT 655.8500 1899.4800 655.9500 1900.0000 ;
    END
  END out[213]
  PIN out[212]
    DIRECTION OUTPUT ;
    USE SIGNAL ;
    PORT
      LAYER M4 ;
        RECT 659.8500 1899.4800 659.9500 1900.0000 ;
    END
  END out[212]
  PIN out[211]
    DIRECTION OUTPUT ;
    USE SIGNAL ;
    PORT
      LAYER M4 ;
        RECT 663.8500 1899.4800 663.9500 1900.0000 ;
    END
  END out[211]
  PIN out[210]
    DIRECTION OUTPUT ;
    USE SIGNAL ;
    PORT
      LAYER M4 ;
        RECT 667.8500 1899.4800 667.9500 1900.0000 ;
    END
  END out[210]
  PIN out[209]
    DIRECTION OUTPUT ;
    USE SIGNAL ;
    PORT
      LAYER M4 ;
        RECT 671.8500 1899.4800 671.9500 1900.0000 ;
    END
  END out[209]
  PIN out[208]
    DIRECTION OUTPUT ;
    USE SIGNAL ;
    PORT
      LAYER M4 ;
        RECT 675.8500 1899.4800 675.9500 1900.0000 ;
    END
  END out[208]
  PIN out[207]
    DIRECTION OUTPUT ;
    USE SIGNAL ;
    PORT
      LAYER M4 ;
        RECT 679.8500 1899.4800 679.9500 1900.0000 ;
    END
  END out[207]
  PIN out[206]
    DIRECTION OUTPUT ;
    USE SIGNAL ;
    PORT
      LAYER M4 ;
        RECT 683.8500 1899.4800 683.9500 1900.0000 ;
    END
  END out[206]
  PIN out[205]
    DIRECTION OUTPUT ;
    USE SIGNAL ;
    PORT
      LAYER M4 ;
        RECT 687.8500 1899.4800 687.9500 1900.0000 ;
    END
  END out[205]
  PIN out[204]
    DIRECTION OUTPUT ;
    USE SIGNAL ;
    PORT
      LAYER M4 ;
        RECT 691.8500 1899.4800 691.9500 1900.0000 ;
    END
  END out[204]
  PIN out[203]
    DIRECTION OUTPUT ;
    USE SIGNAL ;
    PORT
      LAYER M4 ;
        RECT 695.8500 1899.4800 695.9500 1900.0000 ;
    END
  END out[203]
  PIN out[202]
    DIRECTION OUTPUT ;
    USE SIGNAL ;
    PORT
      LAYER M4 ;
        RECT 699.8500 1899.4800 699.9500 1900.0000 ;
    END
  END out[202]
  PIN out[201]
    DIRECTION OUTPUT ;
    USE SIGNAL ;
    PORT
      LAYER M4 ;
        RECT 703.8500 1899.4800 703.9500 1900.0000 ;
    END
  END out[201]
  PIN out[200]
    DIRECTION OUTPUT ;
    USE SIGNAL ;
    PORT
      LAYER M4 ;
        RECT 707.8500 1899.4800 707.9500 1900.0000 ;
    END
  END out[200]
  PIN out[199]
    DIRECTION OUTPUT ;
    USE SIGNAL ;
    PORT
      LAYER M4 ;
        RECT 711.8500 1899.4800 711.9500 1900.0000 ;
    END
  END out[199]
  PIN out[198]
    DIRECTION OUTPUT ;
    USE SIGNAL ;
    PORT
      LAYER M4 ;
        RECT 715.8500 1899.4800 715.9500 1900.0000 ;
    END
  END out[198]
  PIN out[197]
    DIRECTION OUTPUT ;
    USE SIGNAL ;
    PORT
      LAYER M4 ;
        RECT 719.8500 1899.4800 719.9500 1900.0000 ;
    END
  END out[197]
  PIN out[196]
    DIRECTION OUTPUT ;
    USE SIGNAL ;
    PORT
      LAYER M4 ;
        RECT 723.8500 1899.4800 723.9500 1900.0000 ;
    END
  END out[196]
  PIN out[195]
    DIRECTION OUTPUT ;
    USE SIGNAL ;
    PORT
      LAYER M4 ;
        RECT 727.8500 1899.4800 727.9500 1900.0000 ;
    END
  END out[195]
  PIN out[194]
    DIRECTION OUTPUT ;
    USE SIGNAL ;
    PORT
      LAYER M4 ;
        RECT 731.8500 1899.4800 731.9500 1900.0000 ;
    END
  END out[194]
  PIN out[193]
    DIRECTION OUTPUT ;
    USE SIGNAL ;
    PORT
      LAYER M4 ;
        RECT 735.8500 1899.4800 735.9500 1900.0000 ;
    END
  END out[193]
  PIN out[192]
    DIRECTION OUTPUT ;
    USE SIGNAL ;
    PORT
      LAYER M4 ;
        RECT 739.8500 1899.4800 739.9500 1900.0000 ;
    END
  END out[192]
  PIN out[191]
    DIRECTION OUTPUT ;
    USE SIGNAL ;
    PORT
      LAYER M4 ;
        RECT 743.8500 1899.4800 743.9500 1900.0000 ;
    END
  END out[191]
  PIN out[190]
    DIRECTION OUTPUT ;
    USE SIGNAL ;
    PORT
      LAYER M4 ;
        RECT 747.8500 1899.4800 747.9500 1900.0000 ;
    END
  END out[190]
  PIN out[189]
    DIRECTION OUTPUT ;
    USE SIGNAL ;
    PORT
      LAYER M4 ;
        RECT 751.8500 1899.4800 751.9500 1900.0000 ;
    END
  END out[189]
  PIN out[188]
    DIRECTION OUTPUT ;
    USE SIGNAL ;
    PORT
      LAYER M4 ;
        RECT 755.8500 1899.4800 755.9500 1900.0000 ;
    END
  END out[188]
  PIN out[187]
    DIRECTION OUTPUT ;
    USE SIGNAL ;
    PORT
      LAYER M4 ;
        RECT 759.8500 1899.4800 759.9500 1900.0000 ;
    END
  END out[187]
  PIN out[186]
    DIRECTION OUTPUT ;
    USE SIGNAL ;
    PORT
      LAYER M4 ;
        RECT 763.8500 1899.4800 763.9500 1900.0000 ;
    END
  END out[186]
  PIN out[185]
    DIRECTION OUTPUT ;
    USE SIGNAL ;
    PORT
      LAYER M4 ;
        RECT 767.8500 1899.4800 767.9500 1900.0000 ;
    END
  END out[185]
  PIN out[184]
    DIRECTION OUTPUT ;
    USE SIGNAL ;
    PORT
      LAYER M4 ;
        RECT 771.8500 1899.4800 771.9500 1900.0000 ;
    END
  END out[184]
  PIN out[183]
    DIRECTION OUTPUT ;
    USE SIGNAL ;
    PORT
      LAYER M4 ;
        RECT 775.8500 1899.4800 775.9500 1900.0000 ;
    END
  END out[183]
  PIN out[182]
    DIRECTION OUTPUT ;
    USE SIGNAL ;
    PORT
      LAYER M4 ;
        RECT 779.8500 1899.4800 779.9500 1900.0000 ;
    END
  END out[182]
  PIN out[181]
    DIRECTION OUTPUT ;
    USE SIGNAL ;
    PORT
      LAYER M4 ;
        RECT 783.8500 1899.4800 783.9500 1900.0000 ;
    END
  END out[181]
  PIN out[180]
    DIRECTION OUTPUT ;
    USE SIGNAL ;
    PORT
      LAYER M4 ;
        RECT 787.8500 1899.4800 787.9500 1900.0000 ;
    END
  END out[180]
  PIN out[179]
    DIRECTION OUTPUT ;
    USE SIGNAL ;
    PORT
      LAYER M4 ;
        RECT 791.8500 1899.4800 791.9500 1900.0000 ;
    END
  END out[179]
  PIN out[178]
    DIRECTION OUTPUT ;
    USE SIGNAL ;
    PORT
      LAYER M4 ;
        RECT 795.8500 1899.4800 795.9500 1900.0000 ;
    END
  END out[178]
  PIN out[177]
    DIRECTION OUTPUT ;
    USE SIGNAL ;
    PORT
      LAYER M4 ;
        RECT 799.8500 1899.4800 799.9500 1900.0000 ;
    END
  END out[177]
  PIN out[176]
    DIRECTION OUTPUT ;
    USE SIGNAL ;
    PORT
      LAYER M4 ;
        RECT 803.8500 1899.4800 803.9500 1900.0000 ;
    END
  END out[176]
  PIN out[175]
    DIRECTION OUTPUT ;
    USE SIGNAL ;
    PORT
      LAYER M4 ;
        RECT 807.8500 1899.4800 807.9500 1900.0000 ;
    END
  END out[175]
  PIN out[174]
    DIRECTION OUTPUT ;
    USE SIGNAL ;
    PORT
      LAYER M4 ;
        RECT 811.8500 1899.4800 811.9500 1900.0000 ;
    END
  END out[174]
  PIN out[173]
    DIRECTION OUTPUT ;
    USE SIGNAL ;
    PORT
      LAYER M4 ;
        RECT 815.8500 1899.4800 815.9500 1900.0000 ;
    END
  END out[173]
  PIN out[172]
    DIRECTION OUTPUT ;
    USE SIGNAL ;
    PORT
      LAYER M4 ;
        RECT 819.8500 1899.4800 819.9500 1900.0000 ;
    END
  END out[172]
  PIN out[171]
    DIRECTION OUTPUT ;
    USE SIGNAL ;
    PORT
      LAYER M4 ;
        RECT 823.8500 1899.4800 823.9500 1900.0000 ;
    END
  END out[171]
  PIN out[170]
    DIRECTION OUTPUT ;
    USE SIGNAL ;
    PORT
      LAYER M4 ;
        RECT 827.8500 1899.4800 827.9500 1900.0000 ;
    END
  END out[170]
  PIN out[169]
    DIRECTION OUTPUT ;
    USE SIGNAL ;
    PORT
      LAYER M4 ;
        RECT 831.8500 1899.4800 831.9500 1900.0000 ;
    END
  END out[169]
  PIN out[168]
    DIRECTION OUTPUT ;
    USE SIGNAL ;
    PORT
      LAYER M4 ;
        RECT 835.8500 1899.4800 835.9500 1900.0000 ;
    END
  END out[168]
  PIN out[167]
    DIRECTION OUTPUT ;
    USE SIGNAL ;
    PORT
      LAYER M4 ;
        RECT 839.8500 1899.4800 839.9500 1900.0000 ;
    END
  END out[167]
  PIN out[166]
    DIRECTION OUTPUT ;
    USE SIGNAL ;
    PORT
      LAYER M4 ;
        RECT 843.8500 1899.4800 843.9500 1900.0000 ;
    END
  END out[166]
  PIN out[165]
    DIRECTION OUTPUT ;
    USE SIGNAL ;
    PORT
      LAYER M4 ;
        RECT 847.8500 1899.4800 847.9500 1900.0000 ;
    END
  END out[165]
  PIN out[164]
    DIRECTION OUTPUT ;
    USE SIGNAL ;
    PORT
      LAYER M4 ;
        RECT 851.8500 1899.4800 851.9500 1900.0000 ;
    END
  END out[164]
  PIN out[163]
    DIRECTION OUTPUT ;
    USE SIGNAL ;
    PORT
      LAYER M4 ;
        RECT 855.8500 1899.4800 855.9500 1900.0000 ;
    END
  END out[163]
  PIN out[162]
    DIRECTION OUTPUT ;
    USE SIGNAL ;
    PORT
      LAYER M4 ;
        RECT 859.8500 1899.4800 859.9500 1900.0000 ;
    END
  END out[162]
  PIN out[161]
    DIRECTION OUTPUT ;
    USE SIGNAL ;
    PORT
      LAYER M4 ;
        RECT 863.8500 1899.4800 863.9500 1900.0000 ;
    END
  END out[161]
  PIN out[160]
    DIRECTION OUTPUT ;
    USE SIGNAL ;
    PORT
      LAYER M4 ;
        RECT 867.8500 1899.4800 867.9500 1900.0000 ;
    END
  END out[160]
  PIN out[159]
    DIRECTION OUTPUT ;
    USE SIGNAL ;
    PORT
      LAYER M4 ;
        RECT 867.8500 0.0000 867.9500 0.5200 ;
    END
  END out[159]
  PIN out[158]
    DIRECTION OUTPUT ;
    USE SIGNAL ;
    PORT
      LAYER M4 ;
        RECT 863.8500 0.0000 863.9500 0.5200 ;
    END
  END out[158]
  PIN out[157]
    DIRECTION OUTPUT ;
    USE SIGNAL ;
    PORT
      LAYER M4 ;
        RECT 859.8500 0.0000 859.9500 0.5200 ;
    END
  END out[157]
  PIN out[156]
    DIRECTION OUTPUT ;
    USE SIGNAL ;
    PORT
      LAYER M4 ;
        RECT 855.8500 0.0000 855.9500 0.5200 ;
    END
  END out[156]
  PIN out[155]
    DIRECTION OUTPUT ;
    USE SIGNAL ;
    PORT
      LAYER M4 ;
        RECT 851.8500 0.0000 851.9500 0.5200 ;
    END
  END out[155]
  PIN out[154]
    DIRECTION OUTPUT ;
    USE SIGNAL ;
    PORT
      LAYER M4 ;
        RECT 847.8500 0.0000 847.9500 0.5200 ;
    END
  END out[154]
  PIN out[153]
    DIRECTION OUTPUT ;
    USE SIGNAL ;
    PORT
      LAYER M4 ;
        RECT 843.8500 0.0000 843.9500 0.5200 ;
    END
  END out[153]
  PIN out[152]
    DIRECTION OUTPUT ;
    USE SIGNAL ;
    PORT
      LAYER M4 ;
        RECT 839.8500 0.0000 839.9500 0.5200 ;
    END
  END out[152]
  PIN out[151]
    DIRECTION OUTPUT ;
    USE SIGNAL ;
    PORT
      LAYER M4 ;
        RECT 835.8500 0.0000 835.9500 0.5200 ;
    END
  END out[151]
  PIN out[150]
    DIRECTION OUTPUT ;
    USE SIGNAL ;
    PORT
      LAYER M4 ;
        RECT 831.8500 0.0000 831.9500 0.5200 ;
    END
  END out[150]
  PIN out[149]
    DIRECTION OUTPUT ;
    USE SIGNAL ;
    PORT
      LAYER M4 ;
        RECT 827.8500 0.0000 827.9500 0.5200 ;
    END
  END out[149]
  PIN out[148]
    DIRECTION OUTPUT ;
    USE SIGNAL ;
    PORT
      LAYER M4 ;
        RECT 823.8500 0.0000 823.9500 0.5200 ;
    END
  END out[148]
  PIN out[147]
    DIRECTION OUTPUT ;
    USE SIGNAL ;
    PORT
      LAYER M4 ;
        RECT 819.8500 0.0000 819.9500 0.5200 ;
    END
  END out[147]
  PIN out[146]
    DIRECTION OUTPUT ;
    USE SIGNAL ;
    PORT
      LAYER M4 ;
        RECT 815.8500 0.0000 815.9500 0.5200 ;
    END
  END out[146]
  PIN out[145]
    DIRECTION OUTPUT ;
    USE SIGNAL ;
    PORT
      LAYER M4 ;
        RECT 811.8500 0.0000 811.9500 0.5200 ;
    END
  END out[145]
  PIN out[144]
    DIRECTION OUTPUT ;
    USE SIGNAL ;
    PORT
      LAYER M4 ;
        RECT 807.8500 0.0000 807.9500 0.5200 ;
    END
  END out[144]
  PIN out[143]
    DIRECTION OUTPUT ;
    USE SIGNAL ;
    PORT
      LAYER M4 ;
        RECT 803.8500 0.0000 803.9500 0.5200 ;
    END
  END out[143]
  PIN out[142]
    DIRECTION OUTPUT ;
    USE SIGNAL ;
    PORT
      LAYER M4 ;
        RECT 799.8500 0.0000 799.9500 0.5200 ;
    END
  END out[142]
  PIN out[141]
    DIRECTION OUTPUT ;
    USE SIGNAL ;
    PORT
      LAYER M4 ;
        RECT 795.8500 0.0000 795.9500 0.5200 ;
    END
  END out[141]
  PIN out[140]
    DIRECTION OUTPUT ;
    USE SIGNAL ;
    PORT
      LAYER M4 ;
        RECT 791.8500 0.0000 791.9500 0.5200 ;
    END
  END out[140]
  PIN out[139]
    DIRECTION OUTPUT ;
    USE SIGNAL ;
    PORT
      LAYER M4 ;
        RECT 787.8500 0.0000 787.9500 0.5200 ;
    END
  END out[139]
  PIN out[138]
    DIRECTION OUTPUT ;
    USE SIGNAL ;
    PORT
      LAYER M4 ;
        RECT 783.8500 0.0000 783.9500 0.5200 ;
    END
  END out[138]
  PIN out[137]
    DIRECTION OUTPUT ;
    USE SIGNAL ;
    PORT
      LAYER M4 ;
        RECT 779.8500 0.0000 779.9500 0.5200 ;
    END
  END out[137]
  PIN out[136]
    DIRECTION OUTPUT ;
    USE SIGNAL ;
    PORT
      LAYER M4 ;
        RECT 775.8500 0.0000 775.9500 0.5200 ;
    END
  END out[136]
  PIN out[135]
    DIRECTION OUTPUT ;
    USE SIGNAL ;
    PORT
      LAYER M4 ;
        RECT 771.8500 0.0000 771.9500 0.5200 ;
    END
  END out[135]
  PIN out[134]
    DIRECTION OUTPUT ;
    USE SIGNAL ;
    PORT
      LAYER M4 ;
        RECT 767.8500 0.0000 767.9500 0.5200 ;
    END
  END out[134]
  PIN out[133]
    DIRECTION OUTPUT ;
    USE SIGNAL ;
    PORT
      LAYER M4 ;
        RECT 763.8500 0.0000 763.9500 0.5200 ;
    END
  END out[133]
  PIN out[132]
    DIRECTION OUTPUT ;
    USE SIGNAL ;
    PORT
      LAYER M4 ;
        RECT 759.8500 0.0000 759.9500 0.5200 ;
    END
  END out[132]
  PIN out[131]
    DIRECTION OUTPUT ;
    USE SIGNAL ;
    PORT
      LAYER M4 ;
        RECT 755.8500 0.0000 755.9500 0.5200 ;
    END
  END out[131]
  PIN out[130]
    DIRECTION OUTPUT ;
    USE SIGNAL ;
    PORT
      LAYER M4 ;
        RECT 751.8500 0.0000 751.9500 0.5200 ;
    END
  END out[130]
  PIN out[129]
    DIRECTION OUTPUT ;
    USE SIGNAL ;
    PORT
      LAYER M4 ;
        RECT 747.8500 0.0000 747.9500 0.5200 ;
    END
  END out[129]
  PIN out[128]
    DIRECTION OUTPUT ;
    USE SIGNAL ;
    PORT
      LAYER M4 ;
        RECT 743.8500 0.0000 743.9500 0.5200 ;
    END
  END out[128]
  PIN out[127]
    DIRECTION OUTPUT ;
    USE SIGNAL ;
    PORT
      LAYER M4 ;
        RECT 739.8500 0.0000 739.9500 0.5200 ;
    END
  END out[127]
  PIN out[126]
    DIRECTION OUTPUT ;
    USE SIGNAL ;
    PORT
      LAYER M4 ;
        RECT 735.8500 0.0000 735.9500 0.5200 ;
    END
  END out[126]
  PIN out[125]
    DIRECTION OUTPUT ;
    USE SIGNAL ;
    PORT
      LAYER M4 ;
        RECT 731.8500 0.0000 731.9500 0.5200 ;
    END
  END out[125]
  PIN out[124]
    DIRECTION OUTPUT ;
    USE SIGNAL ;
    PORT
      LAYER M4 ;
        RECT 727.8500 0.0000 727.9500 0.5200 ;
    END
  END out[124]
  PIN out[123]
    DIRECTION OUTPUT ;
    USE SIGNAL ;
    PORT
      LAYER M4 ;
        RECT 723.8500 0.0000 723.9500 0.5200 ;
    END
  END out[123]
  PIN out[122]
    DIRECTION OUTPUT ;
    USE SIGNAL ;
    PORT
      LAYER M4 ;
        RECT 719.8500 0.0000 719.9500 0.5200 ;
    END
  END out[122]
  PIN out[121]
    DIRECTION OUTPUT ;
    USE SIGNAL ;
    PORT
      LAYER M4 ;
        RECT 715.8500 0.0000 715.9500 0.5200 ;
    END
  END out[121]
  PIN out[120]
    DIRECTION OUTPUT ;
    USE SIGNAL ;
    PORT
      LAYER M4 ;
        RECT 711.8500 0.0000 711.9500 0.5200 ;
    END
  END out[120]
  PIN out[119]
    DIRECTION OUTPUT ;
    USE SIGNAL ;
    PORT
      LAYER M4 ;
        RECT 707.8500 0.0000 707.9500 0.5200 ;
    END
  END out[119]
  PIN out[118]
    DIRECTION OUTPUT ;
    USE SIGNAL ;
    PORT
      LAYER M4 ;
        RECT 703.8500 0.0000 703.9500 0.5200 ;
    END
  END out[118]
  PIN out[117]
    DIRECTION OUTPUT ;
    USE SIGNAL ;
    PORT
      LAYER M4 ;
        RECT 699.8500 0.0000 699.9500 0.5200 ;
    END
  END out[117]
  PIN out[116]
    DIRECTION OUTPUT ;
    USE SIGNAL ;
    PORT
      LAYER M4 ;
        RECT 695.8500 0.0000 695.9500 0.5200 ;
    END
  END out[116]
  PIN out[115]
    DIRECTION OUTPUT ;
    USE SIGNAL ;
    PORT
      LAYER M4 ;
        RECT 691.8500 0.0000 691.9500 0.5200 ;
    END
  END out[115]
  PIN out[114]
    DIRECTION OUTPUT ;
    USE SIGNAL ;
    PORT
      LAYER M4 ;
        RECT 687.8500 0.0000 687.9500 0.5200 ;
    END
  END out[114]
  PIN out[113]
    DIRECTION OUTPUT ;
    USE SIGNAL ;
    PORT
      LAYER M4 ;
        RECT 683.8500 0.0000 683.9500 0.5200 ;
    END
  END out[113]
  PIN out[112]
    DIRECTION OUTPUT ;
    USE SIGNAL ;
    PORT
      LAYER M4 ;
        RECT 679.8500 0.0000 679.9500 0.5200 ;
    END
  END out[112]
  PIN out[111]
    DIRECTION OUTPUT ;
    USE SIGNAL ;
    PORT
      LAYER M4 ;
        RECT 675.8500 0.0000 675.9500 0.5200 ;
    END
  END out[111]
  PIN out[110]
    DIRECTION OUTPUT ;
    USE SIGNAL ;
    PORT
      LAYER M4 ;
        RECT 671.8500 0.0000 671.9500 0.5200 ;
    END
  END out[110]
  PIN out[109]
    DIRECTION OUTPUT ;
    USE SIGNAL ;
    PORT
      LAYER M4 ;
        RECT 667.8500 0.0000 667.9500 0.5200 ;
    END
  END out[109]
  PIN out[108]
    DIRECTION OUTPUT ;
    USE SIGNAL ;
    PORT
      LAYER M4 ;
        RECT 663.8500 0.0000 663.9500 0.5200 ;
    END
  END out[108]
  PIN out[107]
    DIRECTION OUTPUT ;
    USE SIGNAL ;
    PORT
      LAYER M4 ;
        RECT 659.8500 0.0000 659.9500 0.5200 ;
    END
  END out[107]
  PIN out[106]
    DIRECTION OUTPUT ;
    USE SIGNAL ;
    PORT
      LAYER M4 ;
        RECT 655.8500 0.0000 655.9500 0.5200 ;
    END
  END out[106]
  PIN out[105]
    DIRECTION OUTPUT ;
    USE SIGNAL ;
    PORT
      LAYER M4 ;
        RECT 651.8500 0.0000 651.9500 0.5200 ;
    END
  END out[105]
  PIN out[104]
    DIRECTION OUTPUT ;
    USE SIGNAL ;
    PORT
      LAYER M4 ;
        RECT 647.8500 0.0000 647.9500 0.5200 ;
    END
  END out[104]
  PIN out[103]
    DIRECTION OUTPUT ;
    USE SIGNAL ;
    PORT
      LAYER M4 ;
        RECT 643.8500 0.0000 643.9500 0.5200 ;
    END
  END out[103]
  PIN out[102]
    DIRECTION OUTPUT ;
    USE SIGNAL ;
    PORT
      LAYER M4 ;
        RECT 639.8500 0.0000 639.9500 0.5200 ;
    END
  END out[102]
  PIN out[101]
    DIRECTION OUTPUT ;
    USE SIGNAL ;
    PORT
      LAYER M4 ;
        RECT 635.8500 0.0000 635.9500 0.5200 ;
    END
  END out[101]
  PIN out[100]
    DIRECTION OUTPUT ;
    USE SIGNAL ;
    PORT
      LAYER M4 ;
        RECT 631.8500 0.0000 631.9500 0.5200 ;
    END
  END out[100]
  PIN out[99]
    DIRECTION OUTPUT ;
    USE SIGNAL ;
    PORT
      LAYER M4 ;
        RECT 627.8500 0.0000 627.9500 0.5200 ;
    END
  END out[99]
  PIN out[98]
    DIRECTION OUTPUT ;
    USE SIGNAL ;
    PORT
      LAYER M4 ;
        RECT 623.8500 0.0000 623.9500 0.5200 ;
    END
  END out[98]
  PIN out[97]
    DIRECTION OUTPUT ;
    USE SIGNAL ;
    PORT
      LAYER M4 ;
        RECT 619.8500 0.0000 619.9500 0.5200 ;
    END
  END out[97]
  PIN out[96]
    DIRECTION OUTPUT ;
    USE SIGNAL ;
    PORT
      LAYER M4 ;
        RECT 615.8500 0.0000 615.9500 0.5200 ;
    END
  END out[96]
  PIN out[95]
    DIRECTION OUTPUT ;
    USE SIGNAL ;
    PORT
      LAYER M4 ;
        RECT 611.8500 0.0000 611.9500 0.5200 ;
    END
  END out[95]
  PIN out[94]
    DIRECTION OUTPUT ;
    USE SIGNAL ;
    PORT
      LAYER M4 ;
        RECT 607.8500 0.0000 607.9500 0.5200 ;
    END
  END out[94]
  PIN out[93]
    DIRECTION OUTPUT ;
    USE SIGNAL ;
    PORT
      LAYER M4 ;
        RECT 603.8500 0.0000 603.9500 0.5200 ;
    END
  END out[93]
  PIN out[92]
    DIRECTION OUTPUT ;
    USE SIGNAL ;
    PORT
      LAYER M4 ;
        RECT 599.8500 0.0000 599.9500 0.5200 ;
    END
  END out[92]
  PIN out[91]
    DIRECTION OUTPUT ;
    USE SIGNAL ;
    PORT
      LAYER M4 ;
        RECT 595.8500 0.0000 595.9500 0.5200 ;
    END
  END out[91]
  PIN out[90]
    DIRECTION OUTPUT ;
    USE SIGNAL ;
    PORT
      LAYER M4 ;
        RECT 591.8500 0.0000 591.9500 0.5200 ;
    END
  END out[90]
  PIN out[89]
    DIRECTION OUTPUT ;
    USE SIGNAL ;
    PORT
      LAYER M4 ;
        RECT 587.8500 0.0000 587.9500 0.5200 ;
    END
  END out[89]
  PIN out[88]
    DIRECTION OUTPUT ;
    USE SIGNAL ;
    PORT
      LAYER M4 ;
        RECT 583.8500 0.0000 583.9500 0.5200 ;
    END
  END out[88]
  PIN out[87]
    DIRECTION OUTPUT ;
    USE SIGNAL ;
    PORT
      LAYER M4 ;
        RECT 579.8500 0.0000 579.9500 0.5200 ;
    END
  END out[87]
  PIN out[86]
    DIRECTION OUTPUT ;
    USE SIGNAL ;
    PORT
      LAYER M4 ;
        RECT 575.8500 0.0000 575.9500 0.5200 ;
    END
  END out[86]
  PIN out[85]
    DIRECTION OUTPUT ;
    USE SIGNAL ;
    PORT
      LAYER M4 ;
        RECT 571.8500 0.0000 571.9500 0.5200 ;
    END
  END out[85]
  PIN out[84]
    DIRECTION OUTPUT ;
    USE SIGNAL ;
    PORT
      LAYER M4 ;
        RECT 567.8500 0.0000 567.9500 0.5200 ;
    END
  END out[84]
  PIN out[83]
    DIRECTION OUTPUT ;
    USE SIGNAL ;
    PORT
      LAYER M4 ;
        RECT 563.8500 0.0000 563.9500 0.5200 ;
    END
  END out[83]
  PIN out[82]
    DIRECTION OUTPUT ;
    USE SIGNAL ;
    PORT
      LAYER M4 ;
        RECT 559.8500 0.0000 559.9500 0.5200 ;
    END
  END out[82]
  PIN out[81]
    DIRECTION OUTPUT ;
    USE SIGNAL ;
    PORT
      LAYER M4 ;
        RECT 555.8500 0.0000 555.9500 0.5200 ;
    END
  END out[81]
  PIN out[80]
    DIRECTION OUTPUT ;
    USE SIGNAL ;
    PORT
      LAYER M4 ;
        RECT 551.8500 0.0000 551.9500 0.5200 ;
    END
  END out[80]
  PIN out[79]
    DIRECTION OUTPUT ;
    USE SIGNAL ;
    PORT
      LAYER M4 ;
        RECT 547.8500 0.0000 547.9500 0.5200 ;
    END
  END out[79]
  PIN out[78]
    DIRECTION OUTPUT ;
    USE SIGNAL ;
    PORT
      LAYER M4 ;
        RECT 543.8500 0.0000 543.9500 0.5200 ;
    END
  END out[78]
  PIN out[77]
    DIRECTION OUTPUT ;
    USE SIGNAL ;
    PORT
      LAYER M4 ;
        RECT 539.8500 0.0000 539.9500 0.5200 ;
    END
  END out[77]
  PIN out[76]
    DIRECTION OUTPUT ;
    USE SIGNAL ;
    PORT
      LAYER M4 ;
        RECT 535.8500 0.0000 535.9500 0.5200 ;
    END
  END out[76]
  PIN out[75]
    DIRECTION OUTPUT ;
    USE SIGNAL ;
    PORT
      LAYER M4 ;
        RECT 531.8500 0.0000 531.9500 0.5200 ;
    END
  END out[75]
  PIN out[74]
    DIRECTION OUTPUT ;
    USE SIGNAL ;
    PORT
      LAYER M4 ;
        RECT 527.8500 0.0000 527.9500 0.5200 ;
    END
  END out[74]
  PIN out[73]
    DIRECTION OUTPUT ;
    USE SIGNAL ;
    PORT
      LAYER M4 ;
        RECT 523.8500 0.0000 523.9500 0.5200 ;
    END
  END out[73]
  PIN out[72]
    DIRECTION OUTPUT ;
    USE SIGNAL ;
    PORT
      LAYER M4 ;
        RECT 519.8500 0.0000 519.9500 0.5200 ;
    END
  END out[72]
  PIN out[71]
    DIRECTION OUTPUT ;
    USE SIGNAL ;
    PORT
      LAYER M4 ;
        RECT 515.8500 0.0000 515.9500 0.5200 ;
    END
  END out[71]
  PIN out[70]
    DIRECTION OUTPUT ;
    USE SIGNAL ;
    PORT
      LAYER M4 ;
        RECT 511.8500 0.0000 511.9500 0.5200 ;
    END
  END out[70]
  PIN out[69]
    DIRECTION OUTPUT ;
    USE SIGNAL ;
    PORT
      LAYER M4 ;
        RECT 507.8500 0.0000 507.9500 0.5200 ;
    END
  END out[69]
  PIN out[68]
    DIRECTION OUTPUT ;
    USE SIGNAL ;
    PORT
      LAYER M4 ;
        RECT 503.8500 0.0000 503.9500 0.5200 ;
    END
  END out[68]
  PIN out[67]
    DIRECTION OUTPUT ;
    USE SIGNAL ;
    PORT
      LAYER M4 ;
        RECT 499.8500 0.0000 499.9500 0.5200 ;
    END
  END out[67]
  PIN out[66]
    DIRECTION OUTPUT ;
    USE SIGNAL ;
    PORT
      LAYER M4 ;
        RECT 495.8500 0.0000 495.9500 0.5200 ;
    END
  END out[66]
  PIN out[65]
    DIRECTION OUTPUT ;
    USE SIGNAL ;
    PORT
      LAYER M4 ;
        RECT 491.8500 0.0000 491.9500 0.5200 ;
    END
  END out[65]
  PIN out[64]
    DIRECTION OUTPUT ;
    USE SIGNAL ;
    PORT
      LAYER M4 ;
        RECT 487.8500 0.0000 487.9500 0.5200 ;
    END
  END out[64]
  PIN out[63]
    DIRECTION OUTPUT ;
    USE SIGNAL ;
    PORT
      LAYER M4 ;
        RECT 483.8500 0.0000 483.9500 0.5200 ;
    END
  END out[63]
  PIN out[62]
    DIRECTION OUTPUT ;
    USE SIGNAL ;
    PORT
      LAYER M4 ;
        RECT 479.8500 0.0000 479.9500 0.5200 ;
    END
  END out[62]
  PIN out[61]
    DIRECTION OUTPUT ;
    USE SIGNAL ;
    PORT
      LAYER M4 ;
        RECT 475.8500 0.0000 475.9500 0.5200 ;
    END
  END out[61]
  PIN out[60]
    DIRECTION OUTPUT ;
    USE SIGNAL ;
    PORT
      LAYER M4 ;
        RECT 471.8500 0.0000 471.9500 0.5200 ;
    END
  END out[60]
  PIN out[59]
    DIRECTION OUTPUT ;
    USE SIGNAL ;
    PORT
      LAYER M4 ;
        RECT 467.8500 0.0000 467.9500 0.5200 ;
    END
  END out[59]
  PIN out[58]
    DIRECTION OUTPUT ;
    USE SIGNAL ;
    PORT
      LAYER M4 ;
        RECT 463.8500 0.0000 463.9500 0.5200 ;
    END
  END out[58]
  PIN out[57]
    DIRECTION OUTPUT ;
    USE SIGNAL ;
    PORT
      LAYER M4 ;
        RECT 459.8500 0.0000 459.9500 0.5200 ;
    END
  END out[57]
  PIN out[56]
    DIRECTION OUTPUT ;
    USE SIGNAL ;
    PORT
      LAYER M4 ;
        RECT 455.8500 0.0000 455.9500 0.5200 ;
    END
  END out[56]
  PIN out[55]
    DIRECTION OUTPUT ;
    USE SIGNAL ;
    PORT
      LAYER M4 ;
        RECT 451.8500 0.0000 451.9500 0.5200 ;
    END
  END out[55]
  PIN out[54]
    DIRECTION OUTPUT ;
    USE SIGNAL ;
    PORT
      LAYER M4 ;
        RECT 447.8500 0.0000 447.9500 0.5200 ;
    END
  END out[54]
  PIN out[53]
    DIRECTION OUTPUT ;
    USE SIGNAL ;
    PORT
      LAYER M4 ;
        RECT 443.8500 0.0000 443.9500 0.5200 ;
    END
  END out[53]
  PIN out[52]
    DIRECTION OUTPUT ;
    USE SIGNAL ;
    PORT
      LAYER M4 ;
        RECT 439.8500 0.0000 439.9500 0.5200 ;
    END
  END out[52]
  PIN out[51]
    DIRECTION OUTPUT ;
    USE SIGNAL ;
    PORT
      LAYER M4 ;
        RECT 435.8500 0.0000 435.9500 0.5200 ;
    END
  END out[51]
  PIN out[50]
    DIRECTION OUTPUT ;
    USE SIGNAL ;
    PORT
      LAYER M4 ;
        RECT 431.8500 0.0000 431.9500 0.5200 ;
    END
  END out[50]
  PIN out[49]
    DIRECTION OUTPUT ;
    USE SIGNAL ;
    PORT
      LAYER M4 ;
        RECT 427.8500 0.0000 427.9500 0.5200 ;
    END
  END out[49]
  PIN out[48]
    DIRECTION OUTPUT ;
    USE SIGNAL ;
    PORT
      LAYER M4 ;
        RECT 423.8500 0.0000 423.9500 0.5200 ;
    END
  END out[48]
  PIN out[47]
    DIRECTION OUTPUT ;
    USE SIGNAL ;
    PORT
      LAYER M4 ;
        RECT 419.8500 0.0000 419.9500 0.5200 ;
    END
  END out[47]
  PIN out[46]
    DIRECTION OUTPUT ;
    USE SIGNAL ;
    PORT
      LAYER M4 ;
        RECT 415.8500 0.0000 415.9500 0.5200 ;
    END
  END out[46]
  PIN out[45]
    DIRECTION OUTPUT ;
    USE SIGNAL ;
    PORT
      LAYER M4 ;
        RECT 411.8500 0.0000 411.9500 0.5200 ;
    END
  END out[45]
  PIN out[44]
    DIRECTION OUTPUT ;
    USE SIGNAL ;
    PORT
      LAYER M4 ;
        RECT 407.8500 0.0000 407.9500 0.5200 ;
    END
  END out[44]
  PIN out[43]
    DIRECTION OUTPUT ;
    USE SIGNAL ;
    PORT
      LAYER M4 ;
        RECT 403.8500 0.0000 403.9500 0.5200 ;
    END
  END out[43]
  PIN out[42]
    DIRECTION OUTPUT ;
    USE SIGNAL ;
    PORT
      LAYER M4 ;
        RECT 399.8500 0.0000 399.9500 0.5200 ;
    END
  END out[42]
  PIN out[41]
    DIRECTION OUTPUT ;
    USE SIGNAL ;
    PORT
      LAYER M4 ;
        RECT 395.8500 0.0000 395.9500 0.5200 ;
    END
  END out[41]
  PIN out[40]
    DIRECTION OUTPUT ;
    USE SIGNAL ;
    PORT
      LAYER M4 ;
        RECT 391.8500 0.0000 391.9500 0.5200 ;
    END
  END out[40]
  PIN out[39]
    DIRECTION OUTPUT ;
    USE SIGNAL ;
    PORT
      LAYER M4 ;
        RECT 387.8500 0.0000 387.9500 0.5200 ;
    END
  END out[39]
  PIN out[38]
    DIRECTION OUTPUT ;
    USE SIGNAL ;
    PORT
      LAYER M4 ;
        RECT 383.8500 0.0000 383.9500 0.5200 ;
    END
  END out[38]
  PIN out[37]
    DIRECTION OUTPUT ;
    USE SIGNAL ;
    PORT
      LAYER M4 ;
        RECT 379.8500 0.0000 379.9500 0.5200 ;
    END
  END out[37]
  PIN out[36]
    DIRECTION OUTPUT ;
    USE SIGNAL ;
    PORT
      LAYER M4 ;
        RECT 375.8500 0.0000 375.9500 0.5200 ;
    END
  END out[36]
  PIN out[35]
    DIRECTION OUTPUT ;
    USE SIGNAL ;
    PORT
      LAYER M4 ;
        RECT 371.8500 0.0000 371.9500 0.5200 ;
    END
  END out[35]
  PIN out[34]
    DIRECTION OUTPUT ;
    USE SIGNAL ;
    PORT
      LAYER M4 ;
        RECT 367.8500 0.0000 367.9500 0.5200 ;
    END
  END out[34]
  PIN out[33]
    DIRECTION OUTPUT ;
    USE SIGNAL ;
    PORT
      LAYER M4 ;
        RECT 363.8500 0.0000 363.9500 0.5200 ;
    END
  END out[33]
  PIN out[32]
    DIRECTION OUTPUT ;
    USE SIGNAL ;
    PORT
      LAYER M4 ;
        RECT 359.8500 0.0000 359.9500 0.5200 ;
    END
  END out[32]
  PIN out[31]
    DIRECTION OUTPUT ;
    USE SIGNAL ;
    PORT
      LAYER M4 ;
        RECT 355.8500 0.0000 355.9500 0.5200 ;
    END
  END out[31]
  PIN out[30]
    DIRECTION OUTPUT ;
    USE SIGNAL ;
    PORT
      LAYER M4 ;
        RECT 351.8500 0.0000 351.9500 0.5200 ;
    END
  END out[30]
  PIN out[29]
    DIRECTION OUTPUT ;
    USE SIGNAL ;
    PORT
      LAYER M4 ;
        RECT 347.8500 0.0000 347.9500 0.5200 ;
    END
  END out[29]
  PIN out[28]
    DIRECTION OUTPUT ;
    USE SIGNAL ;
    PORT
      LAYER M4 ;
        RECT 343.8500 0.0000 343.9500 0.5200 ;
    END
  END out[28]
  PIN out[27]
    DIRECTION OUTPUT ;
    USE SIGNAL ;
    PORT
      LAYER M4 ;
        RECT 339.8500 0.0000 339.9500 0.5200 ;
    END
  END out[27]
  PIN out[26]
    DIRECTION OUTPUT ;
    USE SIGNAL ;
    PORT
      LAYER M4 ;
        RECT 335.8500 0.0000 335.9500 0.5200 ;
    END
  END out[26]
  PIN out[25]
    DIRECTION OUTPUT ;
    USE SIGNAL ;
    PORT
      LAYER M4 ;
        RECT 331.8500 0.0000 331.9500 0.5200 ;
    END
  END out[25]
  PIN out[24]
    DIRECTION OUTPUT ;
    USE SIGNAL ;
    PORT
      LAYER M4 ;
        RECT 327.8500 0.0000 327.9500 0.5200 ;
    END
  END out[24]
  PIN out[23]
    DIRECTION OUTPUT ;
    USE SIGNAL ;
    PORT
      LAYER M4 ;
        RECT 323.8500 0.0000 323.9500 0.5200 ;
    END
  END out[23]
  PIN out[22]
    DIRECTION OUTPUT ;
    USE SIGNAL ;
    PORT
      LAYER M4 ;
        RECT 319.8500 0.0000 319.9500 0.5200 ;
    END
  END out[22]
  PIN out[21]
    DIRECTION OUTPUT ;
    USE SIGNAL ;
    PORT
      LAYER M4 ;
        RECT 315.8500 0.0000 315.9500 0.5200 ;
    END
  END out[21]
  PIN out[20]
    DIRECTION OUTPUT ;
    USE SIGNAL ;
    PORT
      LAYER M4 ;
        RECT 311.8500 0.0000 311.9500 0.5200 ;
    END
  END out[20]
  PIN out[19]
    DIRECTION OUTPUT ;
    USE SIGNAL ;
    PORT
      LAYER M4 ;
        RECT 307.8500 0.0000 307.9500 0.5200 ;
    END
  END out[19]
  PIN out[18]
    DIRECTION OUTPUT ;
    USE SIGNAL ;
    PORT
      LAYER M4 ;
        RECT 303.8500 0.0000 303.9500 0.5200 ;
    END
  END out[18]
  PIN out[17]
    DIRECTION OUTPUT ;
    USE SIGNAL ;
    PORT
      LAYER M4 ;
        RECT 299.8500 0.0000 299.9500 0.5200 ;
    END
  END out[17]
  PIN out[16]
    DIRECTION OUTPUT ;
    USE SIGNAL ;
    PORT
      LAYER M4 ;
        RECT 295.8500 0.0000 295.9500 0.5200 ;
    END
  END out[16]
  PIN out[15]
    DIRECTION OUTPUT ;
    USE SIGNAL ;
    PORT
      LAYER M4 ;
        RECT 291.8500 0.0000 291.9500 0.5200 ;
    END
  END out[15]
  PIN out[14]
    DIRECTION OUTPUT ;
    USE SIGNAL ;
    PORT
      LAYER M4 ;
        RECT 287.8500 0.0000 287.9500 0.5200 ;
    END
  END out[14]
  PIN out[13]
    DIRECTION OUTPUT ;
    USE SIGNAL ;
    PORT
      LAYER M4 ;
        RECT 283.8500 0.0000 283.9500 0.5200 ;
    END
  END out[13]
  PIN out[12]
    DIRECTION OUTPUT ;
    USE SIGNAL ;
    PORT
      LAYER M4 ;
        RECT 279.8500 0.0000 279.9500 0.5200 ;
    END
  END out[12]
  PIN out[11]
    DIRECTION OUTPUT ;
    USE SIGNAL ;
    PORT
      LAYER M4 ;
        RECT 275.8500 0.0000 275.9500 0.5200 ;
    END
  END out[11]
  PIN out[10]
    DIRECTION OUTPUT ;
    USE SIGNAL ;
    PORT
      LAYER M4 ;
        RECT 271.8500 0.0000 271.9500 0.5200 ;
    END
  END out[10]
  PIN out[9]
    DIRECTION OUTPUT ;
    USE SIGNAL ;
    PORT
      LAYER M4 ;
        RECT 267.8500 0.0000 267.9500 0.5200 ;
    END
  END out[9]
  PIN out[8]
    DIRECTION OUTPUT ;
    USE SIGNAL ;
    PORT
      LAYER M4 ;
        RECT 263.8500 0.0000 263.9500 0.5200 ;
    END
  END out[8]
  PIN out[7]
    DIRECTION OUTPUT ;
    USE SIGNAL ;
    PORT
      LAYER M4 ;
        RECT 259.8500 0.0000 259.9500 0.5200 ;
    END
  END out[7]
  PIN out[6]
    DIRECTION OUTPUT ;
    USE SIGNAL ;
    PORT
      LAYER M4 ;
        RECT 255.8500 0.0000 255.9500 0.5200 ;
    END
  END out[6]
  PIN out[5]
    DIRECTION OUTPUT ;
    USE SIGNAL ;
    PORT
      LAYER M4 ;
        RECT 251.8500 0.0000 251.9500 0.5200 ;
    END
  END out[5]
  PIN out[4]
    DIRECTION OUTPUT ;
    USE SIGNAL ;
    PORT
      LAYER M4 ;
        RECT 247.8500 0.0000 247.9500 0.5200 ;
    END
  END out[4]
  PIN out[3]
    DIRECTION OUTPUT ;
    USE SIGNAL ;
    PORT
      LAYER M4 ;
        RECT 243.8500 0.0000 243.9500 0.5200 ;
    END
  END out[3]
  PIN out[2]
    DIRECTION OUTPUT ;
    USE SIGNAL ;
    PORT
      LAYER M4 ;
        RECT 239.8500 0.0000 239.9500 0.5200 ;
    END
  END out[2]
  PIN out[1]
    DIRECTION OUTPUT ;
    USE SIGNAL ;
    PORT
      LAYER M4 ;
        RECT 235.8500 0.0000 235.9500 0.5200 ;
    END
  END out[1]
  PIN out[0]
    DIRECTION OUTPUT ;
    USE SIGNAL ;
    PORT
      LAYER M4 ;
        RECT 231.8500 0.0000 231.9500 0.5200 ;
    END
  END out[0]
  PIN test_mode
    DIRECTION INPUT ;
    USE SIGNAL ;
    PORT
      LAYER M3 ;
        RECT 1099.4800 1185.7500 1100.0000 1185.8500 ;
    END
  END test_mode
  PIN clk_scan
    DIRECTION INPUT ;
    USE SIGNAL ;
    PORT
      LAYER M3 ;
        RECT 1099.4800 1189.7500 1100.0000 1189.8500 ;
    END
  END clk_scan
  PIN reset_scan
    DIRECTION INPUT ;
    USE SIGNAL ;
    PORT
      LAYER M3 ;
        RECT 1099.4800 1181.7500 1100.0000 1181.8500 ;
    END
  END reset_scan
  PIN SI[47]
    DIRECTION INPUT ;
    USE SIGNAL ;
    PORT
      LAYER M3 ;
        RECT 1099.4800 985.7500 1100.0000 985.8500 ;
    END
  END SI[47]
  PIN SI[46]
    DIRECTION INPUT ;
    USE SIGNAL ;
    PORT
      LAYER M3 ;
        RECT 1099.4800 981.7500 1100.0000 981.8500 ;
    END
  END SI[46]
  PIN SI[45]
    DIRECTION INPUT ;
    USE SIGNAL ;
    PORT
      LAYER M3 ;
        RECT 1099.4800 977.7500 1100.0000 977.8500 ;
    END
  END SI[45]
  PIN SI[44]
    DIRECTION INPUT ;
    USE SIGNAL ;
    PORT
      LAYER M3 ;
        RECT 1099.4800 973.7500 1100.0000 973.8500 ;
    END
  END SI[44]
  PIN SI[43]
    DIRECTION INPUT ;
    USE SIGNAL ;
    PORT
      LAYER M3 ;
        RECT 1099.4800 969.7500 1100.0000 969.8500 ;
    END
  END SI[43]
  PIN SI[42]
    DIRECTION INPUT ;
    USE SIGNAL ;
    PORT
      LAYER M3 ;
        RECT 1099.4800 965.7500 1100.0000 965.8500 ;
    END
  END SI[42]
  PIN SI[41]
    DIRECTION INPUT ;
    USE SIGNAL ;
    PORT
      LAYER M3 ;
        RECT 1099.4800 961.7500 1100.0000 961.8500 ;
    END
  END SI[41]
  PIN SI[40]
    DIRECTION INPUT ;
    USE SIGNAL ;
    PORT
      LAYER M3 ;
        RECT 1099.4800 957.7500 1100.0000 957.8500 ;
    END
  END SI[40]
  PIN SI[39]
    DIRECTION INPUT ;
    USE SIGNAL ;
    PORT
      LAYER M3 ;
        RECT 1099.4800 953.7500 1100.0000 953.8500 ;
    END
  END SI[39]
  PIN SI[38]
    DIRECTION INPUT ;
    USE SIGNAL ;
    PORT
      LAYER M3 ;
        RECT 1099.4800 949.7500 1100.0000 949.8500 ;
    END
  END SI[38]
  PIN SI[37]
    DIRECTION INPUT ;
    USE SIGNAL ;
    PORT
      LAYER M3 ;
        RECT 1099.4800 945.7500 1100.0000 945.8500 ;
    END
  END SI[37]
  PIN SI[36]
    DIRECTION INPUT ;
    USE SIGNAL ;
    PORT
      LAYER M3 ;
        RECT 1099.4800 941.7500 1100.0000 941.8500 ;
    END
  END SI[36]
  PIN SI[35]
    DIRECTION INPUT ;
    USE SIGNAL ;
    PORT
      LAYER M3 ;
        RECT 1099.4800 937.7500 1100.0000 937.8500 ;
    END
  END SI[35]
  PIN SI[34]
    DIRECTION INPUT ;
    USE SIGNAL ;
    PORT
      LAYER M3 ;
        RECT 1099.4800 933.7500 1100.0000 933.8500 ;
    END
  END SI[34]
  PIN SI[33]
    DIRECTION INPUT ;
    USE SIGNAL ;
    PORT
      LAYER M3 ;
        RECT 1099.4800 929.7500 1100.0000 929.8500 ;
    END
  END SI[33]
  PIN SI[32]
    DIRECTION INPUT ;
    USE SIGNAL ;
    PORT
      LAYER M3 ;
        RECT 1099.4800 925.7500 1100.0000 925.8500 ;
    END
  END SI[32]
  PIN SI[31]
    DIRECTION INPUT ;
    USE SIGNAL ;
    PORT
      LAYER M3 ;
        RECT 1099.4800 921.7500 1100.0000 921.8500 ;
    END
  END SI[31]
  PIN SI[30]
    DIRECTION INPUT ;
    USE SIGNAL ;
    PORT
      LAYER M3 ;
        RECT 1099.4800 917.7500 1100.0000 917.8500 ;
    END
  END SI[30]
  PIN SI[29]
    DIRECTION INPUT ;
    USE SIGNAL ;
    PORT
      LAYER M3 ;
        RECT 1099.4800 913.7500 1100.0000 913.8500 ;
    END
  END SI[29]
  PIN SI[28]
    DIRECTION INPUT ;
    USE SIGNAL ;
    PORT
      LAYER M3 ;
        RECT 1099.4800 909.7500 1100.0000 909.8500 ;
    END
  END SI[28]
  PIN SI[27]
    DIRECTION INPUT ;
    USE SIGNAL ;
    PORT
      LAYER M3 ;
        RECT 1099.4800 905.7500 1100.0000 905.8500 ;
    END
  END SI[27]
  PIN SI[26]
    DIRECTION INPUT ;
    USE SIGNAL ;
    PORT
      LAYER M3 ;
        RECT 1099.4800 901.7500 1100.0000 901.8500 ;
    END
  END SI[26]
  PIN SI[25]
    DIRECTION INPUT ;
    USE SIGNAL ;
    PORT
      LAYER M3 ;
        RECT 1099.4800 897.7500 1100.0000 897.8500 ;
    END
  END SI[25]
  PIN SI[24]
    DIRECTION INPUT ;
    USE SIGNAL ;
    PORT
      LAYER M3 ;
        RECT 1099.4800 893.7500 1100.0000 893.8500 ;
    END
  END SI[24]
  PIN SI[23]
    DIRECTION INPUT ;
    USE SIGNAL ;
    PORT
      LAYER M3 ;
        RECT 1099.4800 889.7500 1100.0000 889.8500 ;
    END
  END SI[23]
  PIN SI[22]
    DIRECTION INPUT ;
    USE SIGNAL ;
    PORT
      LAYER M3 ;
        RECT 1099.4800 885.7500 1100.0000 885.8500 ;
    END
  END SI[22]
  PIN SI[21]
    DIRECTION INPUT ;
    USE SIGNAL ;
    PORT
      LAYER M3 ;
        RECT 1099.4800 881.7500 1100.0000 881.8500 ;
    END
  END SI[21]
  PIN SI[20]
    DIRECTION INPUT ;
    USE SIGNAL ;
    PORT
      LAYER M3 ;
        RECT 1099.4800 877.7500 1100.0000 877.8500 ;
    END
  END SI[20]
  PIN SI[19]
    DIRECTION INPUT ;
    USE SIGNAL ;
    PORT
      LAYER M3 ;
        RECT 1099.4800 873.7500 1100.0000 873.8500 ;
    END
  END SI[19]
  PIN SI[18]
    DIRECTION INPUT ;
    USE SIGNAL ;
    PORT
      LAYER M3 ;
        RECT 1099.4800 869.7500 1100.0000 869.8500 ;
    END
  END SI[18]
  PIN SI[17]
    DIRECTION INPUT ;
    USE SIGNAL ;
    PORT
      LAYER M3 ;
        RECT 1099.4800 865.7500 1100.0000 865.8500 ;
    END
  END SI[17]
  PIN SI[16]
    DIRECTION INPUT ;
    USE SIGNAL ;
    PORT
      LAYER M3 ;
        RECT 1099.4800 861.7500 1100.0000 861.8500 ;
    END
  END SI[16]
  PIN SI[15]
    DIRECTION INPUT ;
    USE SIGNAL ;
    PORT
      LAYER M3 ;
        RECT 1099.4800 857.7500 1100.0000 857.8500 ;
    END
  END SI[15]
  PIN SI[14]
    DIRECTION INPUT ;
    USE SIGNAL ;
    PORT
      LAYER M3 ;
        RECT 1099.4800 853.7500 1100.0000 853.8500 ;
    END
  END SI[14]
  PIN SI[13]
    DIRECTION INPUT ;
    USE SIGNAL ;
    PORT
      LAYER M3 ;
        RECT 1099.4800 849.7500 1100.0000 849.8500 ;
    END
  END SI[13]
  PIN SI[12]
    DIRECTION INPUT ;
    USE SIGNAL ;
    PORT
      LAYER M3 ;
        RECT 1099.4800 845.7500 1100.0000 845.8500 ;
    END
  END SI[12]
  PIN SI[11]
    DIRECTION INPUT ;
    USE SIGNAL ;
    PORT
      LAYER M3 ;
        RECT 1099.4800 841.7500 1100.0000 841.8500 ;
    END
  END SI[11]
  PIN SI[10]
    DIRECTION INPUT ;
    USE SIGNAL ;
    PORT
      LAYER M3 ;
        RECT 1099.4800 837.7500 1100.0000 837.8500 ;
    END
  END SI[10]
  PIN SI[9]
    DIRECTION INPUT ;
    USE SIGNAL ;
    PORT
      LAYER M3 ;
        RECT 1099.4800 833.7500 1100.0000 833.8500 ;
    END
  END SI[9]
  PIN SI[8]
    DIRECTION INPUT ;
    USE SIGNAL ;
    PORT
      LAYER M3 ;
        RECT 1099.4800 829.7500 1100.0000 829.8500 ;
    END
  END SI[8]
  PIN SI[7]
    DIRECTION INPUT ;
    USE SIGNAL ;
    PORT
      LAYER M3 ;
        RECT 1099.4800 825.7500 1100.0000 825.8500 ;
    END
  END SI[7]
  PIN SI[6]
    DIRECTION INPUT ;
    USE SIGNAL ;
    PORT
      LAYER M3 ;
        RECT 1099.4800 821.7500 1100.0000 821.8500 ;
    END
  END SI[6]
  PIN SI[5]
    DIRECTION INPUT ;
    USE SIGNAL ;
    PORT
      LAYER M3 ;
        RECT 1099.4800 817.7500 1100.0000 817.8500 ;
    END
  END SI[5]
  PIN SI[4]
    DIRECTION INPUT ;
    USE SIGNAL ;
    PORT
      LAYER M3 ;
        RECT 1099.4800 813.7500 1100.0000 813.8500 ;
    END
  END SI[4]
  PIN SI[3]
    DIRECTION INPUT ;
    USE SIGNAL ;
    PORT
      LAYER M3 ;
        RECT 1099.4800 809.7500 1100.0000 809.8500 ;
    END
  END SI[3]
  PIN SI[2]
    DIRECTION INPUT ;
    USE SIGNAL ;
    PORT
      LAYER M3 ;
        RECT 1099.4800 805.7500 1100.0000 805.8500 ;
    END
  END SI[2]
  PIN SI[1]
    DIRECTION INPUT ;
    USE SIGNAL ;
    PORT
      LAYER M3 ;
        RECT 1099.4800 801.7500 1100.0000 801.8500 ;
    END
  END SI[1]
  PIN SI[0]
    DIRECTION INPUT ;
    USE SIGNAL ;
    PORT
      LAYER M3 ;
        RECT 1099.4800 797.7500 1100.0000 797.8500 ;
    END
  END SI[0]
  PIN SE
    DIRECTION INPUT ;
    USE SIGNAL ;
    PORT
      LAYER M3 ;
        RECT 1099.4800 793.7500 1100.0000 793.8500 ;
    END
  END SE
  PIN SO[47]
    DIRECTION OUTPUT ;
    USE SIGNAL ;
    PORT
      LAYER M3 ;
        RECT 1099.4800 1177.7500 1100.0000 1177.8500 ;
    END
  END SO[47]
  PIN SO[46]
    DIRECTION OUTPUT ;
    USE SIGNAL ;
    PORT
      LAYER M3 ;
        RECT 1099.4800 1173.7500 1100.0000 1173.8500 ;
    END
  END SO[46]
  PIN SO[45]
    DIRECTION OUTPUT ;
    USE SIGNAL ;
    PORT
      LAYER M3 ;
        RECT 1099.4800 1169.7500 1100.0000 1169.8500 ;
    END
  END SO[45]
  PIN SO[44]
    DIRECTION OUTPUT ;
    USE SIGNAL ;
    PORT
      LAYER M3 ;
        RECT 1099.4800 1165.7500 1100.0000 1165.8500 ;
    END
  END SO[44]
  PIN SO[43]
    DIRECTION OUTPUT ;
    USE SIGNAL ;
    PORT
      LAYER M3 ;
        RECT 1099.4800 1161.7500 1100.0000 1161.8500 ;
    END
  END SO[43]
  PIN SO[42]
    DIRECTION OUTPUT ;
    USE SIGNAL ;
    PORT
      LAYER M3 ;
        RECT 1099.4800 1157.7500 1100.0000 1157.8500 ;
    END
  END SO[42]
  PIN SO[41]
    DIRECTION OUTPUT ;
    USE SIGNAL ;
    PORT
      LAYER M3 ;
        RECT 1099.4800 1153.7500 1100.0000 1153.8500 ;
    END
  END SO[41]
  PIN SO[40]
    DIRECTION OUTPUT ;
    USE SIGNAL ;
    PORT
      LAYER M3 ;
        RECT 1099.4800 1149.7500 1100.0000 1149.8500 ;
    END
  END SO[40]
  PIN SO[39]
    DIRECTION OUTPUT ;
    USE SIGNAL ;
    PORT
      LAYER M3 ;
        RECT 1099.4800 1145.7500 1100.0000 1145.8500 ;
    END
  END SO[39]
  PIN SO[38]
    DIRECTION OUTPUT ;
    USE SIGNAL ;
    PORT
      LAYER M3 ;
        RECT 1099.4800 1141.7500 1100.0000 1141.8500 ;
    END
  END SO[38]
  PIN SO[37]
    DIRECTION OUTPUT ;
    USE SIGNAL ;
    PORT
      LAYER M3 ;
        RECT 1099.4800 1137.7500 1100.0000 1137.8500 ;
    END
  END SO[37]
  PIN SO[36]
    DIRECTION OUTPUT ;
    USE SIGNAL ;
    PORT
      LAYER M3 ;
        RECT 1099.4800 1133.7500 1100.0000 1133.8500 ;
    END
  END SO[36]
  PIN SO[35]
    DIRECTION OUTPUT ;
    USE SIGNAL ;
    PORT
      LAYER M3 ;
        RECT 1099.4800 1129.7500 1100.0000 1129.8500 ;
    END
  END SO[35]
  PIN SO[34]
    DIRECTION OUTPUT ;
    USE SIGNAL ;
    PORT
      LAYER M3 ;
        RECT 1099.4800 1125.7500 1100.0000 1125.8500 ;
    END
  END SO[34]
  PIN SO[33]
    DIRECTION OUTPUT ;
    USE SIGNAL ;
    PORT
      LAYER M3 ;
        RECT 1099.4800 1121.7500 1100.0000 1121.8500 ;
    END
  END SO[33]
  PIN SO[32]
    DIRECTION OUTPUT ;
    USE SIGNAL ;
    PORT
      LAYER M3 ;
        RECT 1099.4800 1117.7500 1100.0000 1117.8500 ;
    END
  END SO[32]
  PIN SO[31]
    DIRECTION OUTPUT ;
    USE SIGNAL ;
    PORT
      LAYER M3 ;
        RECT 1099.4800 1113.7500 1100.0000 1113.8500 ;
    END
  END SO[31]
  PIN SO[30]
    DIRECTION OUTPUT ;
    USE SIGNAL ;
    PORT
      LAYER M3 ;
        RECT 1099.4800 1109.7500 1100.0000 1109.8500 ;
    END
  END SO[30]
  PIN SO[29]
    DIRECTION OUTPUT ;
    USE SIGNAL ;
    PORT
      LAYER M3 ;
        RECT 1099.4800 1105.7500 1100.0000 1105.8500 ;
    END
  END SO[29]
  PIN SO[28]
    DIRECTION OUTPUT ;
    USE SIGNAL ;
    PORT
      LAYER M3 ;
        RECT 1099.4800 1101.7500 1100.0000 1101.8500 ;
    END
  END SO[28]
  PIN SO[27]
    DIRECTION OUTPUT ;
    USE SIGNAL ;
    PORT
      LAYER M3 ;
        RECT 1099.4800 1097.7500 1100.0000 1097.8500 ;
    END
  END SO[27]
  PIN SO[26]
    DIRECTION OUTPUT ;
    USE SIGNAL ;
    PORT
      LAYER M3 ;
        RECT 1099.4800 1093.7500 1100.0000 1093.8500 ;
    END
  END SO[26]
  PIN SO[25]
    DIRECTION OUTPUT ;
    USE SIGNAL ;
    PORT
      LAYER M3 ;
        RECT 1099.4800 1089.7500 1100.0000 1089.8500 ;
    END
  END SO[25]
  PIN SO[24]
    DIRECTION OUTPUT ;
    USE SIGNAL ;
    PORT
      LAYER M3 ;
        RECT 1099.4800 1085.7500 1100.0000 1085.8500 ;
    END
  END SO[24]
  PIN SO[23]
    DIRECTION OUTPUT ;
    USE SIGNAL ;
    PORT
      LAYER M3 ;
        RECT 1099.4800 1081.7500 1100.0000 1081.8500 ;
    END
  END SO[23]
  PIN SO[22]
    DIRECTION OUTPUT ;
    USE SIGNAL ;
    PORT
      LAYER M3 ;
        RECT 1099.4800 1077.7500 1100.0000 1077.8500 ;
    END
  END SO[22]
  PIN SO[21]
    DIRECTION OUTPUT ;
    USE SIGNAL ;
    PORT
      LAYER M3 ;
        RECT 1099.4800 1073.7500 1100.0000 1073.8500 ;
    END
  END SO[21]
  PIN SO[20]
    DIRECTION OUTPUT ;
    USE SIGNAL ;
    PORT
      LAYER M3 ;
        RECT 1099.4800 1069.7500 1100.0000 1069.8500 ;
    END
  END SO[20]
  PIN SO[19]
    DIRECTION OUTPUT ;
    USE SIGNAL ;
    PORT
      LAYER M3 ;
        RECT 1099.4800 1065.7500 1100.0000 1065.8500 ;
    END
  END SO[19]
  PIN SO[18]
    DIRECTION OUTPUT ;
    USE SIGNAL ;
    PORT
      LAYER M3 ;
        RECT 1099.4800 1061.7500 1100.0000 1061.8500 ;
    END
  END SO[18]
  PIN SO[17]
    DIRECTION OUTPUT ;
    USE SIGNAL ;
    PORT
      LAYER M3 ;
        RECT 1099.4800 1057.7500 1100.0000 1057.8500 ;
    END
  END SO[17]
  PIN SO[16]
    DIRECTION OUTPUT ;
    USE SIGNAL ;
    PORT
      LAYER M3 ;
        RECT 1099.4800 1053.7500 1100.0000 1053.8500 ;
    END
  END SO[16]
  PIN SO[15]
    DIRECTION OUTPUT ;
    USE SIGNAL ;
    PORT
      LAYER M3 ;
        RECT 1099.4800 1049.7500 1100.0000 1049.8500 ;
    END
  END SO[15]
  PIN SO[14]
    DIRECTION OUTPUT ;
    USE SIGNAL ;
    PORT
      LAYER M3 ;
        RECT 1099.4800 1045.7500 1100.0000 1045.8500 ;
    END
  END SO[14]
  PIN SO[13]
    DIRECTION OUTPUT ;
    USE SIGNAL ;
    PORT
      LAYER M3 ;
        RECT 1099.4800 1041.7500 1100.0000 1041.8500 ;
    END
  END SO[13]
  PIN SO[12]
    DIRECTION OUTPUT ;
    USE SIGNAL ;
    PORT
      LAYER M3 ;
        RECT 1099.4800 1037.7500 1100.0000 1037.8500 ;
    END
  END SO[12]
  PIN SO[11]
    DIRECTION OUTPUT ;
    USE SIGNAL ;
    PORT
      LAYER M3 ;
        RECT 1099.4800 1033.7500 1100.0000 1033.8500 ;
    END
  END SO[11]
  PIN SO[10]
    DIRECTION OUTPUT ;
    USE SIGNAL ;
    PORT
      LAYER M3 ;
        RECT 1099.4800 1029.7500 1100.0000 1029.8500 ;
    END
  END SO[10]
  PIN SO[9]
    DIRECTION OUTPUT ;
    USE SIGNAL ;
    PORT
      LAYER M3 ;
        RECT 1099.4800 1025.7500 1100.0000 1025.8500 ;
    END
  END SO[9]
  PIN SO[8]
    DIRECTION OUTPUT ;
    USE SIGNAL ;
    PORT
      LAYER M3 ;
        RECT 1099.4800 1021.7500 1100.0000 1021.8500 ;
    END
  END SO[8]
  PIN SO[7]
    DIRECTION OUTPUT ;
    USE SIGNAL ;
    PORT
      LAYER M3 ;
        RECT 1099.4800 1017.7500 1100.0000 1017.8500 ;
    END
  END SO[7]
  PIN SO[6]
    DIRECTION OUTPUT ;
    USE SIGNAL ;
    PORT
      LAYER M3 ;
        RECT 1099.4800 1013.7500 1100.0000 1013.8500 ;
    END
  END SO[6]
  PIN SO[5]
    DIRECTION OUTPUT ;
    USE SIGNAL ;
    PORT
      LAYER M3 ;
        RECT 1099.4800 1009.7500 1100.0000 1009.8500 ;
    END
  END SO[5]
  PIN SO[4]
    DIRECTION OUTPUT ;
    USE SIGNAL ;
    PORT
      LAYER M3 ;
        RECT 1099.4800 1005.7500 1100.0000 1005.8500 ;
    END
  END SO[4]
  PIN SO[3]
    DIRECTION OUTPUT ;
    USE SIGNAL ;
    PORT
      LAYER M3 ;
        RECT 1099.4800 1001.7500 1100.0000 1001.8500 ;
    END
  END SO[3]
  PIN SO[2]
    DIRECTION OUTPUT ;
    USE SIGNAL ;
    PORT
      LAYER M3 ;
        RECT 1099.4800 997.7500 1100.0000 997.8500 ;
    END
  END SO[2]
  PIN SO[1]
    DIRECTION OUTPUT ;
    USE SIGNAL ;
    PORT
      LAYER M3 ;
        RECT 1099.4800 993.7500 1100.0000 993.8500 ;
    END
  END SO[1]
  PIN SO[0]
    DIRECTION OUTPUT ;
    USE SIGNAL ;
    PORT
      LAYER M3 ;
        RECT 1099.4800 989.7500 1100.0000 989.8500 ;
    END
  END SO[0]
  OBS
    LAYER M1 ;
      RECT 0.0000 0.0000 1100.0000 1900.0000 ;
    LAYER M2 ;
      RECT 0.0000 0.0000 1100.0000 1900.0000 ;
    LAYER M3 ;
      RECT 0.0000 1208.3500 1100.0000 1900.0000 ;
      RECT 0.6200 1208.0500 1100.0000 1208.3500 ;
      RECT 0.0000 1204.3500 1100.0000 1208.0500 ;
      RECT 0.6200 1204.0500 1100.0000 1204.3500 ;
      RECT 0.0000 1200.3500 1100.0000 1204.0500 ;
      RECT 0.6200 1200.0500 1100.0000 1200.3500 ;
      RECT 0.0000 1196.3500 1100.0000 1200.0500 ;
      RECT 0.6200 1196.0500 1100.0000 1196.3500 ;
      RECT 0.0000 1192.3500 1100.0000 1196.0500 ;
      RECT 0.6200 1192.0500 1100.0000 1192.3500 ;
      RECT 0.0000 1189.9500 1100.0000 1192.0500 ;
      RECT 0.0000 1189.6500 1099.3800 1189.9500 ;
      RECT 0.0000 1188.3500 1100.0000 1189.6500 ;
      RECT 0.6200 1188.0500 1100.0000 1188.3500 ;
      RECT 0.0000 1185.9500 1100.0000 1188.0500 ;
      RECT 0.0000 1185.6500 1099.3800 1185.9500 ;
      RECT 0.0000 1184.3500 1100.0000 1185.6500 ;
      RECT 0.6200 1184.0500 1100.0000 1184.3500 ;
      RECT 0.0000 1181.9500 1100.0000 1184.0500 ;
      RECT 0.0000 1181.6500 1099.3800 1181.9500 ;
      RECT 0.0000 1180.3500 1100.0000 1181.6500 ;
      RECT 0.6200 1180.0500 1100.0000 1180.3500 ;
      RECT 0.0000 1177.9500 1100.0000 1180.0500 ;
      RECT 0.0000 1177.6500 1099.3800 1177.9500 ;
      RECT 0.0000 1176.3500 1100.0000 1177.6500 ;
      RECT 0.6200 1176.0500 1100.0000 1176.3500 ;
      RECT 0.0000 1173.9500 1100.0000 1176.0500 ;
      RECT 0.0000 1173.6500 1099.3800 1173.9500 ;
      RECT 0.0000 1172.3500 1100.0000 1173.6500 ;
      RECT 0.6200 1172.0500 1100.0000 1172.3500 ;
      RECT 0.0000 1169.9500 1100.0000 1172.0500 ;
      RECT 0.0000 1169.6500 1099.3800 1169.9500 ;
      RECT 0.0000 1168.3500 1100.0000 1169.6500 ;
      RECT 0.6200 1168.0500 1100.0000 1168.3500 ;
      RECT 0.0000 1165.9500 1100.0000 1168.0500 ;
      RECT 0.0000 1165.6500 1099.3800 1165.9500 ;
      RECT 0.0000 1164.3500 1100.0000 1165.6500 ;
      RECT 0.6200 1164.0500 1100.0000 1164.3500 ;
      RECT 0.0000 1161.9500 1100.0000 1164.0500 ;
      RECT 0.0000 1161.6500 1099.3800 1161.9500 ;
      RECT 0.0000 1160.3500 1100.0000 1161.6500 ;
      RECT 0.6200 1160.0500 1100.0000 1160.3500 ;
      RECT 0.0000 1157.9500 1100.0000 1160.0500 ;
      RECT 0.0000 1157.6500 1099.3800 1157.9500 ;
      RECT 0.0000 1156.3500 1100.0000 1157.6500 ;
      RECT 0.6200 1156.0500 1100.0000 1156.3500 ;
      RECT 0.0000 1153.9500 1100.0000 1156.0500 ;
      RECT 0.0000 1153.6500 1099.3800 1153.9500 ;
      RECT 0.0000 1152.3500 1100.0000 1153.6500 ;
      RECT 0.6200 1152.0500 1100.0000 1152.3500 ;
      RECT 0.0000 1149.9500 1100.0000 1152.0500 ;
      RECT 0.0000 1149.6500 1099.3800 1149.9500 ;
      RECT 0.0000 1148.3500 1100.0000 1149.6500 ;
      RECT 0.6200 1148.0500 1100.0000 1148.3500 ;
      RECT 0.0000 1145.9500 1100.0000 1148.0500 ;
      RECT 0.0000 1145.6500 1099.3800 1145.9500 ;
      RECT 0.0000 1144.3500 1100.0000 1145.6500 ;
      RECT 0.6200 1144.0500 1100.0000 1144.3500 ;
      RECT 0.0000 1141.9500 1100.0000 1144.0500 ;
      RECT 0.0000 1141.6500 1099.3800 1141.9500 ;
      RECT 0.0000 1140.3500 1100.0000 1141.6500 ;
      RECT 0.6200 1140.0500 1100.0000 1140.3500 ;
      RECT 0.0000 1137.9500 1100.0000 1140.0500 ;
      RECT 0.0000 1137.6500 1099.3800 1137.9500 ;
      RECT 0.0000 1136.3500 1100.0000 1137.6500 ;
      RECT 0.6200 1136.0500 1100.0000 1136.3500 ;
      RECT 0.0000 1133.9500 1100.0000 1136.0500 ;
      RECT 0.0000 1133.6500 1099.3800 1133.9500 ;
      RECT 0.0000 1132.3500 1100.0000 1133.6500 ;
      RECT 0.6200 1132.0500 1100.0000 1132.3500 ;
      RECT 0.0000 1129.9500 1100.0000 1132.0500 ;
      RECT 0.0000 1129.6500 1099.3800 1129.9500 ;
      RECT 0.0000 1128.3500 1100.0000 1129.6500 ;
      RECT 0.6200 1128.0500 1100.0000 1128.3500 ;
      RECT 0.0000 1125.9500 1100.0000 1128.0500 ;
      RECT 0.0000 1125.6500 1099.3800 1125.9500 ;
      RECT 0.0000 1124.3500 1100.0000 1125.6500 ;
      RECT 0.6200 1124.0500 1100.0000 1124.3500 ;
      RECT 0.0000 1121.9500 1100.0000 1124.0500 ;
      RECT 0.0000 1121.6500 1099.3800 1121.9500 ;
      RECT 0.0000 1120.3500 1100.0000 1121.6500 ;
      RECT 0.6200 1120.0500 1100.0000 1120.3500 ;
      RECT 0.0000 1117.9500 1100.0000 1120.0500 ;
      RECT 0.0000 1117.6500 1099.3800 1117.9500 ;
      RECT 0.0000 1116.3500 1100.0000 1117.6500 ;
      RECT 0.6200 1116.0500 1100.0000 1116.3500 ;
      RECT 0.0000 1113.9500 1100.0000 1116.0500 ;
      RECT 0.0000 1113.6500 1099.3800 1113.9500 ;
      RECT 0.0000 1112.3500 1100.0000 1113.6500 ;
      RECT 0.6200 1112.0500 1100.0000 1112.3500 ;
      RECT 0.0000 1109.9500 1100.0000 1112.0500 ;
      RECT 0.0000 1109.6500 1099.3800 1109.9500 ;
      RECT 0.0000 1108.3500 1100.0000 1109.6500 ;
      RECT 0.6200 1108.0500 1100.0000 1108.3500 ;
      RECT 0.0000 1105.9500 1100.0000 1108.0500 ;
      RECT 0.0000 1105.6500 1099.3800 1105.9500 ;
      RECT 0.0000 1104.3500 1100.0000 1105.6500 ;
      RECT 0.6200 1104.0500 1100.0000 1104.3500 ;
      RECT 0.0000 1101.9500 1100.0000 1104.0500 ;
      RECT 0.0000 1101.6500 1099.3800 1101.9500 ;
      RECT 0.0000 1100.3500 1100.0000 1101.6500 ;
      RECT 0.6200 1100.0500 1100.0000 1100.3500 ;
      RECT 0.0000 1097.9500 1100.0000 1100.0500 ;
      RECT 0.0000 1097.6500 1099.3800 1097.9500 ;
      RECT 0.0000 1096.3500 1100.0000 1097.6500 ;
      RECT 0.6200 1096.0500 1100.0000 1096.3500 ;
      RECT 0.0000 1093.9500 1100.0000 1096.0500 ;
      RECT 0.0000 1093.6500 1099.3800 1093.9500 ;
      RECT 0.0000 1092.3500 1100.0000 1093.6500 ;
      RECT 0.6200 1092.0500 1100.0000 1092.3500 ;
      RECT 0.0000 1089.9500 1100.0000 1092.0500 ;
      RECT 0.0000 1089.6500 1099.3800 1089.9500 ;
      RECT 0.0000 1088.3500 1100.0000 1089.6500 ;
      RECT 0.6200 1088.0500 1100.0000 1088.3500 ;
      RECT 0.0000 1085.9500 1100.0000 1088.0500 ;
      RECT 0.0000 1085.6500 1099.3800 1085.9500 ;
      RECT 0.0000 1084.3500 1100.0000 1085.6500 ;
      RECT 0.6200 1084.0500 1100.0000 1084.3500 ;
      RECT 0.0000 1081.9500 1100.0000 1084.0500 ;
      RECT 0.0000 1081.6500 1099.3800 1081.9500 ;
      RECT 0.0000 1080.3500 1100.0000 1081.6500 ;
      RECT 0.6200 1080.0500 1100.0000 1080.3500 ;
      RECT 0.0000 1077.9500 1100.0000 1080.0500 ;
      RECT 0.0000 1077.6500 1099.3800 1077.9500 ;
      RECT 0.0000 1076.3500 1100.0000 1077.6500 ;
      RECT 0.6200 1076.0500 1100.0000 1076.3500 ;
      RECT 0.0000 1073.9500 1100.0000 1076.0500 ;
      RECT 0.0000 1073.6500 1099.3800 1073.9500 ;
      RECT 0.0000 1072.3500 1100.0000 1073.6500 ;
      RECT 0.6200 1072.0500 1100.0000 1072.3500 ;
      RECT 0.0000 1069.9500 1100.0000 1072.0500 ;
      RECT 0.0000 1069.6500 1099.3800 1069.9500 ;
      RECT 0.0000 1068.3500 1100.0000 1069.6500 ;
      RECT 0.6200 1068.0500 1100.0000 1068.3500 ;
      RECT 0.0000 1065.9500 1100.0000 1068.0500 ;
      RECT 0.0000 1065.6500 1099.3800 1065.9500 ;
      RECT 0.0000 1064.3500 1100.0000 1065.6500 ;
      RECT 0.6200 1064.0500 1100.0000 1064.3500 ;
      RECT 0.0000 1061.9500 1100.0000 1064.0500 ;
      RECT 0.0000 1061.6500 1099.3800 1061.9500 ;
      RECT 0.0000 1060.3500 1100.0000 1061.6500 ;
      RECT 0.6200 1060.0500 1100.0000 1060.3500 ;
      RECT 0.0000 1057.9500 1100.0000 1060.0500 ;
      RECT 0.0000 1057.6500 1099.3800 1057.9500 ;
      RECT 0.0000 1056.3500 1100.0000 1057.6500 ;
      RECT 0.6200 1056.0500 1100.0000 1056.3500 ;
      RECT 0.0000 1053.9500 1100.0000 1056.0500 ;
      RECT 0.0000 1053.6500 1099.3800 1053.9500 ;
      RECT 0.0000 1052.3500 1100.0000 1053.6500 ;
      RECT 0.6200 1052.0500 1100.0000 1052.3500 ;
      RECT 0.0000 1049.9500 1100.0000 1052.0500 ;
      RECT 0.0000 1049.6500 1099.3800 1049.9500 ;
      RECT 0.0000 1048.3500 1100.0000 1049.6500 ;
      RECT 0.6200 1048.0500 1100.0000 1048.3500 ;
      RECT 0.0000 1045.9500 1100.0000 1048.0500 ;
      RECT 0.0000 1045.6500 1099.3800 1045.9500 ;
      RECT 0.0000 1044.3500 1100.0000 1045.6500 ;
      RECT 0.6200 1044.0500 1100.0000 1044.3500 ;
      RECT 0.0000 1041.9500 1100.0000 1044.0500 ;
      RECT 0.0000 1041.6500 1099.3800 1041.9500 ;
      RECT 0.0000 1040.3500 1100.0000 1041.6500 ;
      RECT 0.6200 1040.0500 1100.0000 1040.3500 ;
      RECT 0.0000 1037.9500 1100.0000 1040.0500 ;
      RECT 0.0000 1037.6500 1099.3800 1037.9500 ;
      RECT 0.0000 1036.3500 1100.0000 1037.6500 ;
      RECT 0.6200 1036.0500 1100.0000 1036.3500 ;
      RECT 0.0000 1033.9500 1100.0000 1036.0500 ;
      RECT 0.0000 1033.6500 1099.3800 1033.9500 ;
      RECT 0.0000 1032.3500 1100.0000 1033.6500 ;
      RECT 0.6200 1032.0500 1100.0000 1032.3500 ;
      RECT 0.0000 1029.9500 1100.0000 1032.0500 ;
      RECT 0.0000 1029.6500 1099.3800 1029.9500 ;
      RECT 0.0000 1028.3500 1100.0000 1029.6500 ;
      RECT 0.6200 1028.0500 1100.0000 1028.3500 ;
      RECT 0.0000 1025.9500 1100.0000 1028.0500 ;
      RECT 0.0000 1025.6500 1099.3800 1025.9500 ;
      RECT 0.0000 1024.3500 1100.0000 1025.6500 ;
      RECT 0.6200 1024.0500 1100.0000 1024.3500 ;
      RECT 0.0000 1021.9500 1100.0000 1024.0500 ;
      RECT 0.0000 1021.6500 1099.3800 1021.9500 ;
      RECT 0.0000 1020.3500 1100.0000 1021.6500 ;
      RECT 0.6200 1020.0500 1100.0000 1020.3500 ;
      RECT 0.0000 1017.9500 1100.0000 1020.0500 ;
      RECT 0.0000 1017.6500 1099.3800 1017.9500 ;
      RECT 0.0000 1016.3500 1100.0000 1017.6500 ;
      RECT 0.6200 1016.0500 1100.0000 1016.3500 ;
      RECT 0.0000 1013.9500 1100.0000 1016.0500 ;
      RECT 0.0000 1013.6500 1099.3800 1013.9500 ;
      RECT 0.0000 1012.3500 1100.0000 1013.6500 ;
      RECT 0.6200 1012.0500 1100.0000 1012.3500 ;
      RECT 0.0000 1009.9500 1100.0000 1012.0500 ;
      RECT 0.0000 1009.6500 1099.3800 1009.9500 ;
      RECT 0.0000 1008.3500 1100.0000 1009.6500 ;
      RECT 0.6200 1008.0500 1100.0000 1008.3500 ;
      RECT 0.0000 1005.9500 1100.0000 1008.0500 ;
      RECT 0.0000 1005.6500 1099.3800 1005.9500 ;
      RECT 0.0000 1004.3500 1100.0000 1005.6500 ;
      RECT 0.6200 1004.0500 1100.0000 1004.3500 ;
      RECT 0.0000 1001.9500 1100.0000 1004.0500 ;
      RECT 0.0000 1001.6500 1099.3800 1001.9500 ;
      RECT 0.0000 1000.3500 1100.0000 1001.6500 ;
      RECT 0.6200 1000.0500 1100.0000 1000.3500 ;
      RECT 0.0000 997.9500 1100.0000 1000.0500 ;
      RECT 0.0000 997.6500 1099.3800 997.9500 ;
      RECT 0.0000 996.3500 1100.0000 997.6500 ;
      RECT 0.6200 996.0500 1100.0000 996.3500 ;
      RECT 0.0000 993.9500 1100.0000 996.0500 ;
      RECT 0.0000 993.6500 1099.3800 993.9500 ;
      RECT 0.0000 992.3500 1100.0000 993.6500 ;
      RECT 0.6200 992.0500 1100.0000 992.3500 ;
      RECT 0.0000 989.9500 1100.0000 992.0500 ;
      RECT 0.0000 989.6500 1099.3800 989.9500 ;
      RECT 0.0000 988.3500 1100.0000 989.6500 ;
      RECT 0.6200 988.0500 1100.0000 988.3500 ;
      RECT 0.0000 985.9500 1100.0000 988.0500 ;
      RECT 0.0000 985.6500 1099.3800 985.9500 ;
      RECT 0.0000 984.3500 1100.0000 985.6500 ;
      RECT 0.6200 984.0500 1100.0000 984.3500 ;
      RECT 0.0000 981.9500 1100.0000 984.0500 ;
      RECT 0.0000 981.6500 1099.3800 981.9500 ;
      RECT 0.0000 980.3500 1100.0000 981.6500 ;
      RECT 0.6200 980.0500 1100.0000 980.3500 ;
      RECT 0.0000 977.9500 1100.0000 980.0500 ;
      RECT 0.0000 977.6500 1099.3800 977.9500 ;
      RECT 0.0000 976.3500 1100.0000 977.6500 ;
      RECT 0.6200 976.0500 1100.0000 976.3500 ;
      RECT 0.0000 973.9500 1100.0000 976.0500 ;
      RECT 0.0000 973.6500 1099.3800 973.9500 ;
      RECT 0.0000 972.3500 1100.0000 973.6500 ;
      RECT 0.6200 972.0500 1100.0000 972.3500 ;
      RECT 0.0000 969.9500 1100.0000 972.0500 ;
      RECT 0.0000 969.6500 1099.3800 969.9500 ;
      RECT 0.0000 968.3500 1100.0000 969.6500 ;
      RECT 0.6200 968.0500 1100.0000 968.3500 ;
      RECT 0.0000 965.9500 1100.0000 968.0500 ;
      RECT 0.0000 965.6500 1099.3800 965.9500 ;
      RECT 0.0000 964.3500 1100.0000 965.6500 ;
      RECT 0.6200 964.0500 1100.0000 964.3500 ;
      RECT 0.0000 961.9500 1100.0000 964.0500 ;
      RECT 0.0000 961.6500 1099.3800 961.9500 ;
      RECT 0.0000 960.3500 1100.0000 961.6500 ;
      RECT 0.6200 960.0500 1100.0000 960.3500 ;
      RECT 0.0000 957.9500 1100.0000 960.0500 ;
      RECT 0.0000 957.6500 1099.3800 957.9500 ;
      RECT 0.0000 956.3500 1100.0000 957.6500 ;
      RECT 0.6200 956.0500 1100.0000 956.3500 ;
      RECT 0.0000 953.9500 1100.0000 956.0500 ;
      RECT 0.0000 953.6500 1099.3800 953.9500 ;
      RECT 0.0000 952.3500 1100.0000 953.6500 ;
      RECT 0.6200 952.0500 1100.0000 952.3500 ;
      RECT 0.0000 949.9500 1100.0000 952.0500 ;
      RECT 0.0000 949.6500 1099.3800 949.9500 ;
      RECT 0.0000 948.3500 1100.0000 949.6500 ;
      RECT 0.6200 948.0500 1100.0000 948.3500 ;
      RECT 0.0000 945.9500 1100.0000 948.0500 ;
      RECT 0.0000 945.6500 1099.3800 945.9500 ;
      RECT 0.0000 944.3500 1100.0000 945.6500 ;
      RECT 0.6200 944.0500 1100.0000 944.3500 ;
      RECT 0.0000 941.9500 1100.0000 944.0500 ;
      RECT 0.0000 941.6500 1099.3800 941.9500 ;
      RECT 0.0000 940.3500 1100.0000 941.6500 ;
      RECT 0.6200 940.0500 1100.0000 940.3500 ;
      RECT 0.0000 937.9500 1100.0000 940.0500 ;
      RECT 0.0000 937.6500 1099.3800 937.9500 ;
      RECT 0.0000 936.3500 1100.0000 937.6500 ;
      RECT 0.6200 936.0500 1100.0000 936.3500 ;
      RECT 0.0000 933.9500 1100.0000 936.0500 ;
      RECT 0.0000 933.6500 1099.3800 933.9500 ;
      RECT 0.0000 932.3500 1100.0000 933.6500 ;
      RECT 0.6200 932.0500 1100.0000 932.3500 ;
      RECT 0.0000 929.9500 1100.0000 932.0500 ;
      RECT 0.0000 929.6500 1099.3800 929.9500 ;
      RECT 0.0000 928.3500 1100.0000 929.6500 ;
      RECT 0.6200 928.0500 1100.0000 928.3500 ;
      RECT 0.0000 925.9500 1100.0000 928.0500 ;
      RECT 0.0000 925.6500 1099.3800 925.9500 ;
      RECT 0.0000 924.3500 1100.0000 925.6500 ;
      RECT 0.6200 924.0500 1100.0000 924.3500 ;
      RECT 0.0000 921.9500 1100.0000 924.0500 ;
      RECT 0.0000 921.6500 1099.3800 921.9500 ;
      RECT 0.0000 920.3500 1100.0000 921.6500 ;
      RECT 0.6200 920.0500 1100.0000 920.3500 ;
      RECT 0.0000 917.9500 1100.0000 920.0500 ;
      RECT 0.0000 917.6500 1099.3800 917.9500 ;
      RECT 0.0000 916.3500 1100.0000 917.6500 ;
      RECT 0.6200 916.0500 1100.0000 916.3500 ;
      RECT 0.0000 913.9500 1100.0000 916.0500 ;
      RECT 0.0000 913.6500 1099.3800 913.9500 ;
      RECT 0.0000 912.3500 1100.0000 913.6500 ;
      RECT 0.6200 912.0500 1100.0000 912.3500 ;
      RECT 0.0000 909.9500 1100.0000 912.0500 ;
      RECT 0.0000 909.6500 1099.3800 909.9500 ;
      RECT 0.0000 908.3500 1100.0000 909.6500 ;
      RECT 0.6200 908.0500 1100.0000 908.3500 ;
      RECT 0.0000 905.9500 1100.0000 908.0500 ;
      RECT 0.0000 905.6500 1099.3800 905.9500 ;
      RECT 0.0000 904.3500 1100.0000 905.6500 ;
      RECT 0.6200 904.0500 1100.0000 904.3500 ;
      RECT 0.0000 901.9500 1100.0000 904.0500 ;
      RECT 0.0000 901.6500 1099.3800 901.9500 ;
      RECT 0.0000 900.3500 1100.0000 901.6500 ;
      RECT 0.6200 900.0500 1100.0000 900.3500 ;
      RECT 0.0000 897.9500 1100.0000 900.0500 ;
      RECT 0.0000 897.6500 1099.3800 897.9500 ;
      RECT 0.0000 896.3500 1100.0000 897.6500 ;
      RECT 0.6200 896.0500 1100.0000 896.3500 ;
      RECT 0.0000 893.9500 1100.0000 896.0500 ;
      RECT 0.0000 893.6500 1099.3800 893.9500 ;
      RECT 0.0000 892.3500 1100.0000 893.6500 ;
      RECT 0.6200 892.0500 1100.0000 892.3500 ;
      RECT 0.0000 889.9500 1100.0000 892.0500 ;
      RECT 0.0000 889.6500 1099.3800 889.9500 ;
      RECT 0.0000 888.3500 1100.0000 889.6500 ;
      RECT 0.6200 888.0500 1100.0000 888.3500 ;
      RECT 0.0000 885.9500 1100.0000 888.0500 ;
      RECT 0.0000 885.6500 1099.3800 885.9500 ;
      RECT 0.0000 884.3500 1100.0000 885.6500 ;
      RECT 0.6200 884.0500 1100.0000 884.3500 ;
      RECT 0.0000 881.9500 1100.0000 884.0500 ;
      RECT 0.0000 881.6500 1099.3800 881.9500 ;
      RECT 0.0000 880.3500 1100.0000 881.6500 ;
      RECT 0.6200 880.0500 1100.0000 880.3500 ;
      RECT 0.0000 877.9500 1100.0000 880.0500 ;
      RECT 0.0000 877.6500 1099.3800 877.9500 ;
      RECT 0.0000 876.3500 1100.0000 877.6500 ;
      RECT 0.6200 876.0500 1100.0000 876.3500 ;
      RECT 0.0000 873.9500 1100.0000 876.0500 ;
      RECT 0.0000 873.6500 1099.3800 873.9500 ;
      RECT 0.0000 872.3500 1100.0000 873.6500 ;
      RECT 0.6200 872.0500 1100.0000 872.3500 ;
      RECT 0.0000 869.9500 1100.0000 872.0500 ;
      RECT 0.0000 869.6500 1099.3800 869.9500 ;
      RECT 0.0000 868.3500 1100.0000 869.6500 ;
      RECT 0.6200 868.0500 1100.0000 868.3500 ;
      RECT 0.0000 865.9500 1100.0000 868.0500 ;
      RECT 0.0000 865.6500 1099.3800 865.9500 ;
      RECT 0.0000 864.3500 1100.0000 865.6500 ;
      RECT 0.6200 864.0500 1100.0000 864.3500 ;
      RECT 0.0000 861.9500 1100.0000 864.0500 ;
      RECT 0.0000 861.6500 1099.3800 861.9500 ;
      RECT 0.0000 860.3500 1100.0000 861.6500 ;
      RECT 0.6200 860.0500 1100.0000 860.3500 ;
      RECT 0.0000 857.9500 1100.0000 860.0500 ;
      RECT 0.0000 857.6500 1099.3800 857.9500 ;
      RECT 0.0000 856.3500 1100.0000 857.6500 ;
      RECT 0.6200 856.0500 1100.0000 856.3500 ;
      RECT 0.0000 853.9500 1100.0000 856.0500 ;
      RECT 0.0000 853.6500 1099.3800 853.9500 ;
      RECT 0.0000 852.3500 1100.0000 853.6500 ;
      RECT 0.6200 852.0500 1100.0000 852.3500 ;
      RECT 0.0000 849.9500 1100.0000 852.0500 ;
      RECT 0.0000 849.6500 1099.3800 849.9500 ;
      RECT 0.0000 848.3500 1100.0000 849.6500 ;
      RECT 0.6200 848.0500 1100.0000 848.3500 ;
      RECT 0.0000 845.9500 1100.0000 848.0500 ;
      RECT 0.0000 845.6500 1099.3800 845.9500 ;
      RECT 0.0000 844.3500 1100.0000 845.6500 ;
      RECT 0.6200 844.0500 1100.0000 844.3500 ;
      RECT 0.0000 841.9500 1100.0000 844.0500 ;
      RECT 0.0000 841.6500 1099.3800 841.9500 ;
      RECT 0.0000 840.3500 1100.0000 841.6500 ;
      RECT 0.6200 840.0500 1100.0000 840.3500 ;
      RECT 0.0000 837.9500 1100.0000 840.0500 ;
      RECT 0.0000 837.6500 1099.3800 837.9500 ;
      RECT 0.0000 836.3500 1100.0000 837.6500 ;
      RECT 0.6200 836.0500 1100.0000 836.3500 ;
      RECT 0.0000 833.9500 1100.0000 836.0500 ;
      RECT 0.0000 833.6500 1099.3800 833.9500 ;
      RECT 0.0000 832.3500 1100.0000 833.6500 ;
      RECT 0.6200 832.0500 1100.0000 832.3500 ;
      RECT 0.0000 829.9500 1100.0000 832.0500 ;
      RECT 0.0000 829.6500 1099.3800 829.9500 ;
      RECT 0.0000 828.3500 1100.0000 829.6500 ;
      RECT 0.6200 828.0500 1100.0000 828.3500 ;
      RECT 0.0000 825.9500 1100.0000 828.0500 ;
      RECT 0.0000 825.6500 1099.3800 825.9500 ;
      RECT 0.0000 824.3500 1100.0000 825.6500 ;
      RECT 0.6200 824.0500 1100.0000 824.3500 ;
      RECT 0.0000 821.9500 1100.0000 824.0500 ;
      RECT 0.0000 821.6500 1099.3800 821.9500 ;
      RECT 0.0000 820.3500 1100.0000 821.6500 ;
      RECT 0.6200 820.0500 1100.0000 820.3500 ;
      RECT 0.0000 817.9500 1100.0000 820.0500 ;
      RECT 0.0000 817.6500 1099.3800 817.9500 ;
      RECT 0.0000 816.3500 1100.0000 817.6500 ;
      RECT 0.6200 816.0500 1100.0000 816.3500 ;
      RECT 0.0000 813.9500 1100.0000 816.0500 ;
      RECT 0.0000 813.6500 1099.3800 813.9500 ;
      RECT 0.0000 812.3500 1100.0000 813.6500 ;
      RECT 0.6200 812.0500 1100.0000 812.3500 ;
      RECT 0.0000 809.9500 1100.0000 812.0500 ;
      RECT 0.0000 809.6500 1099.3800 809.9500 ;
      RECT 0.0000 808.3500 1100.0000 809.6500 ;
      RECT 0.6200 808.0500 1100.0000 808.3500 ;
      RECT 0.0000 805.9500 1100.0000 808.0500 ;
      RECT 0.0000 805.6500 1099.3800 805.9500 ;
      RECT 0.0000 804.3500 1100.0000 805.6500 ;
      RECT 0.6200 804.0500 1100.0000 804.3500 ;
      RECT 0.0000 801.9500 1100.0000 804.0500 ;
      RECT 0.0000 801.6500 1099.3800 801.9500 ;
      RECT 0.0000 800.3500 1100.0000 801.6500 ;
      RECT 0.6200 800.0500 1100.0000 800.3500 ;
      RECT 0.0000 797.9500 1100.0000 800.0500 ;
      RECT 0.0000 797.6500 1099.3800 797.9500 ;
      RECT 0.0000 796.3500 1100.0000 797.6500 ;
      RECT 0.6200 796.0500 1100.0000 796.3500 ;
      RECT 0.0000 793.9500 1100.0000 796.0500 ;
      RECT 0.0000 793.6500 1099.3800 793.9500 ;
      RECT 0.0000 792.3500 1100.0000 793.6500 ;
      RECT 0.6200 792.0500 1100.0000 792.3500 ;
      RECT 0.0000 789.9500 1100.0000 792.0500 ;
      RECT 0.0000 789.6500 1099.3800 789.9500 ;
      RECT 0.0000 788.3500 1100.0000 789.6500 ;
      RECT 0.6200 788.0500 1100.0000 788.3500 ;
      RECT 0.0000 785.9500 1100.0000 788.0500 ;
      RECT 0.0000 785.6500 1099.3800 785.9500 ;
      RECT 0.0000 784.3500 1100.0000 785.6500 ;
      RECT 0.6200 784.0500 1100.0000 784.3500 ;
      RECT 0.0000 781.9500 1100.0000 784.0500 ;
      RECT 0.0000 781.6500 1099.3800 781.9500 ;
      RECT 0.0000 780.3500 1100.0000 781.6500 ;
      RECT 0.6200 780.0500 1100.0000 780.3500 ;
      RECT 0.0000 777.9500 1100.0000 780.0500 ;
      RECT 0.0000 777.6500 1099.3800 777.9500 ;
      RECT 0.0000 776.3500 1100.0000 777.6500 ;
      RECT 0.6200 776.0500 1100.0000 776.3500 ;
      RECT 0.0000 773.9500 1100.0000 776.0500 ;
      RECT 0.0000 773.6500 1099.3800 773.9500 ;
      RECT 0.0000 772.3500 1100.0000 773.6500 ;
      RECT 0.6200 772.0500 1100.0000 772.3500 ;
      RECT 0.0000 769.9500 1100.0000 772.0500 ;
      RECT 0.0000 769.6500 1099.3800 769.9500 ;
      RECT 0.0000 768.3500 1100.0000 769.6500 ;
      RECT 0.6200 768.0500 1100.0000 768.3500 ;
      RECT 0.0000 765.9500 1100.0000 768.0500 ;
      RECT 0.0000 765.6500 1099.3800 765.9500 ;
      RECT 0.0000 764.3500 1100.0000 765.6500 ;
      RECT 0.6200 764.0500 1100.0000 764.3500 ;
      RECT 0.0000 761.9500 1100.0000 764.0500 ;
      RECT 0.0000 761.6500 1099.3800 761.9500 ;
      RECT 0.0000 760.3500 1100.0000 761.6500 ;
      RECT 0.6200 760.0500 1100.0000 760.3500 ;
      RECT 0.0000 757.9500 1100.0000 760.0500 ;
      RECT 0.0000 757.6500 1099.3800 757.9500 ;
      RECT 0.0000 756.3500 1100.0000 757.6500 ;
      RECT 0.6200 756.0500 1100.0000 756.3500 ;
      RECT 0.0000 753.9500 1100.0000 756.0500 ;
      RECT 0.0000 753.6500 1099.3800 753.9500 ;
      RECT 0.0000 752.3500 1100.0000 753.6500 ;
      RECT 0.6200 752.0500 1100.0000 752.3500 ;
      RECT 0.0000 749.9500 1100.0000 752.0500 ;
      RECT 0.0000 749.6500 1099.3800 749.9500 ;
      RECT 0.0000 748.3500 1100.0000 749.6500 ;
      RECT 0.6200 748.0500 1100.0000 748.3500 ;
      RECT 0.0000 745.9500 1100.0000 748.0500 ;
      RECT 0.0000 745.6500 1099.3800 745.9500 ;
      RECT 0.0000 744.3500 1100.0000 745.6500 ;
      RECT 0.6200 744.0500 1100.0000 744.3500 ;
      RECT 0.0000 741.9500 1100.0000 744.0500 ;
      RECT 0.0000 741.6500 1099.3800 741.9500 ;
      RECT 0.0000 740.3500 1100.0000 741.6500 ;
      RECT 0.6200 740.0500 1100.0000 740.3500 ;
      RECT 0.0000 737.9500 1100.0000 740.0500 ;
      RECT 0.0000 737.6500 1099.3800 737.9500 ;
      RECT 0.0000 736.3500 1100.0000 737.6500 ;
      RECT 0.6200 736.0500 1100.0000 736.3500 ;
      RECT 0.0000 733.9500 1100.0000 736.0500 ;
      RECT 0.0000 733.6500 1099.3800 733.9500 ;
      RECT 0.0000 732.3500 1100.0000 733.6500 ;
      RECT 0.6200 732.0500 1100.0000 732.3500 ;
      RECT 0.0000 729.9500 1100.0000 732.0500 ;
      RECT 0.0000 729.6500 1099.3800 729.9500 ;
      RECT 0.0000 728.3500 1100.0000 729.6500 ;
      RECT 0.6200 728.0500 1100.0000 728.3500 ;
      RECT 0.0000 725.9500 1100.0000 728.0500 ;
      RECT 0.0000 725.6500 1099.3800 725.9500 ;
      RECT 0.0000 724.3500 1100.0000 725.6500 ;
      RECT 0.6200 724.0500 1100.0000 724.3500 ;
      RECT 0.0000 721.9500 1100.0000 724.0500 ;
      RECT 0.0000 721.6500 1099.3800 721.9500 ;
      RECT 0.0000 720.3500 1100.0000 721.6500 ;
      RECT 0.6200 720.0500 1100.0000 720.3500 ;
      RECT 0.0000 717.9500 1100.0000 720.0500 ;
      RECT 0.0000 717.6500 1099.3800 717.9500 ;
      RECT 0.0000 716.3500 1100.0000 717.6500 ;
      RECT 0.6200 716.0500 1100.0000 716.3500 ;
      RECT 0.0000 713.9500 1100.0000 716.0500 ;
      RECT 0.0000 713.6500 1099.3800 713.9500 ;
      RECT 0.0000 712.3500 1100.0000 713.6500 ;
      RECT 0.6200 712.0500 1100.0000 712.3500 ;
      RECT 0.0000 709.9500 1100.0000 712.0500 ;
      RECT 0.0000 709.6500 1099.3800 709.9500 ;
      RECT 0.0000 708.3500 1100.0000 709.6500 ;
      RECT 0.6200 708.0500 1100.0000 708.3500 ;
      RECT 0.0000 704.3500 1100.0000 708.0500 ;
      RECT 0.6200 704.0500 1100.0000 704.3500 ;
      RECT 0.0000 700.3500 1100.0000 704.0500 ;
      RECT 0.6200 700.0500 1100.0000 700.3500 ;
      RECT 0.0000 696.3500 1100.0000 700.0500 ;
      RECT 0.6200 696.0500 1100.0000 696.3500 ;
      RECT 0.0000 692.3500 1100.0000 696.0500 ;
      RECT 0.6200 692.0500 1100.0000 692.3500 ;
      RECT 0.0000 0.0000 1100.0000 692.0500 ;
    LAYER M4 ;
      RECT 868.0500 1899.3800 1100.0000 1900.0000 ;
      RECT 864.0500 1899.3800 867.7500 1900.0000 ;
      RECT 860.0500 1899.3800 863.7500 1900.0000 ;
      RECT 856.0500 1899.3800 859.7500 1900.0000 ;
      RECT 852.0500 1899.3800 855.7500 1900.0000 ;
      RECT 848.0500 1899.3800 851.7500 1900.0000 ;
      RECT 844.0500 1899.3800 847.7500 1900.0000 ;
      RECT 840.0500 1899.3800 843.7500 1900.0000 ;
      RECT 836.0500 1899.3800 839.7500 1900.0000 ;
      RECT 832.0500 1899.3800 835.7500 1900.0000 ;
      RECT 828.0500 1899.3800 831.7500 1900.0000 ;
      RECT 824.0500 1899.3800 827.7500 1900.0000 ;
      RECT 820.0500 1899.3800 823.7500 1900.0000 ;
      RECT 816.0500 1899.3800 819.7500 1900.0000 ;
      RECT 812.0500 1899.3800 815.7500 1900.0000 ;
      RECT 808.0500 1899.3800 811.7500 1900.0000 ;
      RECT 804.0500 1899.3800 807.7500 1900.0000 ;
      RECT 800.0500 1899.3800 803.7500 1900.0000 ;
      RECT 796.0500 1899.3800 799.7500 1900.0000 ;
      RECT 792.0500 1899.3800 795.7500 1900.0000 ;
      RECT 788.0500 1899.3800 791.7500 1900.0000 ;
      RECT 784.0500 1899.3800 787.7500 1900.0000 ;
      RECT 780.0500 1899.3800 783.7500 1900.0000 ;
      RECT 776.0500 1899.3800 779.7500 1900.0000 ;
      RECT 772.0500 1899.3800 775.7500 1900.0000 ;
      RECT 768.0500 1899.3800 771.7500 1900.0000 ;
      RECT 764.0500 1899.3800 767.7500 1900.0000 ;
      RECT 760.0500 1899.3800 763.7500 1900.0000 ;
      RECT 756.0500 1899.3800 759.7500 1900.0000 ;
      RECT 752.0500 1899.3800 755.7500 1900.0000 ;
      RECT 748.0500 1899.3800 751.7500 1900.0000 ;
      RECT 744.0500 1899.3800 747.7500 1900.0000 ;
      RECT 740.0500 1899.3800 743.7500 1900.0000 ;
      RECT 736.0500 1899.3800 739.7500 1900.0000 ;
      RECT 732.0500 1899.3800 735.7500 1900.0000 ;
      RECT 728.0500 1899.3800 731.7500 1900.0000 ;
      RECT 724.0500 1899.3800 727.7500 1900.0000 ;
      RECT 720.0500 1899.3800 723.7500 1900.0000 ;
      RECT 716.0500 1899.3800 719.7500 1900.0000 ;
      RECT 712.0500 1899.3800 715.7500 1900.0000 ;
      RECT 708.0500 1899.3800 711.7500 1900.0000 ;
      RECT 704.0500 1899.3800 707.7500 1900.0000 ;
      RECT 700.0500 1899.3800 703.7500 1900.0000 ;
      RECT 696.0500 1899.3800 699.7500 1900.0000 ;
      RECT 692.0500 1899.3800 695.7500 1900.0000 ;
      RECT 688.0500 1899.3800 691.7500 1900.0000 ;
      RECT 684.0500 1899.3800 687.7500 1900.0000 ;
      RECT 680.0500 1899.3800 683.7500 1900.0000 ;
      RECT 676.0500 1899.3800 679.7500 1900.0000 ;
      RECT 672.0500 1899.3800 675.7500 1900.0000 ;
      RECT 668.0500 1899.3800 671.7500 1900.0000 ;
      RECT 664.0500 1899.3800 667.7500 1900.0000 ;
      RECT 660.0500 1899.3800 663.7500 1900.0000 ;
      RECT 656.0500 1899.3800 659.7500 1900.0000 ;
      RECT 652.0500 1899.3800 655.7500 1900.0000 ;
      RECT 648.0500 1899.3800 651.7500 1900.0000 ;
      RECT 644.0500 1899.3800 647.7500 1900.0000 ;
      RECT 640.0500 1899.3800 643.7500 1900.0000 ;
      RECT 636.0500 1899.3800 639.7500 1900.0000 ;
      RECT 632.0500 1899.3800 635.7500 1900.0000 ;
      RECT 628.0500 1899.3800 631.7500 1900.0000 ;
      RECT 624.0500 1899.3800 627.7500 1900.0000 ;
      RECT 620.0500 1899.3800 623.7500 1900.0000 ;
      RECT 616.0500 1899.3800 619.7500 1900.0000 ;
      RECT 612.0500 1899.3800 615.7500 1900.0000 ;
      RECT 608.0500 1899.3800 611.7500 1900.0000 ;
      RECT 604.0500 1899.3800 607.7500 1900.0000 ;
      RECT 600.0500 1899.3800 603.7500 1900.0000 ;
      RECT 596.0500 1899.3800 599.7500 1900.0000 ;
      RECT 592.0500 1899.3800 595.7500 1900.0000 ;
      RECT 588.0500 1899.3800 591.7500 1900.0000 ;
      RECT 584.0500 1899.3800 587.7500 1900.0000 ;
      RECT 580.0500 1899.3800 583.7500 1900.0000 ;
      RECT 576.0500 1899.3800 579.7500 1900.0000 ;
      RECT 572.0500 1899.3800 575.7500 1900.0000 ;
      RECT 568.0500 1899.3800 571.7500 1900.0000 ;
      RECT 564.0500 1899.3800 567.7500 1900.0000 ;
      RECT 560.0500 1899.3800 563.7500 1900.0000 ;
      RECT 556.0500 1899.3800 559.7500 1900.0000 ;
      RECT 552.0500 1899.3800 555.7500 1900.0000 ;
      RECT 548.0500 1899.3800 551.7500 1900.0000 ;
      RECT 544.0500 1899.3800 547.7500 1900.0000 ;
      RECT 540.0500 1899.3800 543.7500 1900.0000 ;
      RECT 536.0500 1899.3800 539.7500 1900.0000 ;
      RECT 532.0500 1899.3800 535.7500 1900.0000 ;
      RECT 528.0500 1899.3800 531.7500 1900.0000 ;
      RECT 524.0500 1899.3800 527.7500 1900.0000 ;
      RECT 520.0500 1899.3800 523.7500 1900.0000 ;
      RECT 516.0500 1899.3800 519.7500 1900.0000 ;
      RECT 512.0500 1899.3800 515.7500 1900.0000 ;
      RECT 508.0500 1899.3800 511.7500 1900.0000 ;
      RECT 504.0500 1899.3800 507.7500 1900.0000 ;
      RECT 500.0500 1899.3800 503.7500 1900.0000 ;
      RECT 496.0500 1899.3800 499.7500 1900.0000 ;
      RECT 492.0500 1899.3800 495.7500 1900.0000 ;
      RECT 488.0500 1899.3800 491.7500 1900.0000 ;
      RECT 484.0500 1899.3800 487.7500 1900.0000 ;
      RECT 480.0500 1899.3800 483.7500 1900.0000 ;
      RECT 476.0500 1899.3800 479.7500 1900.0000 ;
      RECT 472.0500 1899.3800 475.7500 1900.0000 ;
      RECT 468.0500 1899.3800 471.7500 1900.0000 ;
      RECT 464.0500 1899.3800 467.7500 1900.0000 ;
      RECT 460.0500 1899.3800 463.7500 1900.0000 ;
      RECT 456.0500 1899.3800 459.7500 1900.0000 ;
      RECT 452.0500 1899.3800 455.7500 1900.0000 ;
      RECT 448.0500 1899.3800 451.7500 1900.0000 ;
      RECT 444.0500 1899.3800 447.7500 1900.0000 ;
      RECT 440.0500 1899.3800 443.7500 1900.0000 ;
      RECT 436.0500 1899.3800 439.7500 1900.0000 ;
      RECT 432.0500 1899.3800 435.7500 1900.0000 ;
      RECT 428.0500 1899.3800 431.7500 1900.0000 ;
      RECT 424.0500 1899.3800 427.7500 1900.0000 ;
      RECT 420.0500 1899.3800 423.7500 1900.0000 ;
      RECT 416.0500 1899.3800 419.7500 1900.0000 ;
      RECT 412.0500 1899.3800 415.7500 1900.0000 ;
      RECT 408.0500 1899.3800 411.7500 1900.0000 ;
      RECT 404.0500 1899.3800 407.7500 1900.0000 ;
      RECT 400.0500 1899.3800 403.7500 1900.0000 ;
      RECT 396.0500 1899.3800 399.7500 1900.0000 ;
      RECT 392.0500 1899.3800 395.7500 1900.0000 ;
      RECT 388.0500 1899.3800 391.7500 1900.0000 ;
      RECT 384.0500 1899.3800 387.7500 1900.0000 ;
      RECT 380.0500 1899.3800 383.7500 1900.0000 ;
      RECT 376.0500 1899.3800 379.7500 1900.0000 ;
      RECT 372.0500 1899.3800 375.7500 1900.0000 ;
      RECT 368.0500 1899.3800 371.7500 1900.0000 ;
      RECT 364.0500 1899.3800 367.7500 1900.0000 ;
      RECT 360.0500 1899.3800 363.7500 1900.0000 ;
      RECT 356.0500 1899.3800 359.7500 1900.0000 ;
      RECT 352.0500 1899.3800 355.7500 1900.0000 ;
      RECT 348.0500 1899.3800 351.7500 1900.0000 ;
      RECT 344.0500 1899.3800 347.7500 1900.0000 ;
      RECT 340.0500 1899.3800 343.7500 1900.0000 ;
      RECT 336.0500 1899.3800 339.7500 1900.0000 ;
      RECT 332.0500 1899.3800 335.7500 1900.0000 ;
      RECT 328.0500 1899.3800 331.7500 1900.0000 ;
      RECT 324.0500 1899.3800 327.7500 1900.0000 ;
      RECT 320.0500 1899.3800 323.7500 1900.0000 ;
      RECT 316.0500 1899.3800 319.7500 1900.0000 ;
      RECT 312.0500 1899.3800 315.7500 1900.0000 ;
      RECT 308.0500 1899.3800 311.7500 1900.0000 ;
      RECT 304.0500 1899.3800 307.7500 1900.0000 ;
      RECT 300.0500 1899.3800 303.7500 1900.0000 ;
      RECT 296.0500 1899.3800 299.7500 1900.0000 ;
      RECT 292.0500 1899.3800 295.7500 1900.0000 ;
      RECT 288.0500 1899.3800 291.7500 1900.0000 ;
      RECT 284.0500 1899.3800 287.7500 1900.0000 ;
      RECT 280.0500 1899.3800 283.7500 1900.0000 ;
      RECT 276.0500 1899.3800 279.7500 1900.0000 ;
      RECT 272.0500 1899.3800 275.7500 1900.0000 ;
      RECT 268.0500 1899.3800 271.7500 1900.0000 ;
      RECT 264.0500 1899.3800 267.7500 1900.0000 ;
      RECT 260.0500 1899.3800 263.7500 1900.0000 ;
      RECT 256.0500 1899.3800 259.7500 1900.0000 ;
      RECT 252.0500 1899.3800 255.7500 1900.0000 ;
      RECT 248.0500 1899.3800 251.7500 1900.0000 ;
      RECT 244.0500 1899.3800 247.7500 1900.0000 ;
      RECT 240.0500 1899.3800 243.7500 1900.0000 ;
      RECT 236.0500 1899.3800 239.7500 1900.0000 ;
      RECT 232.0500 1899.3800 235.7500 1900.0000 ;
      RECT 0.0000 1899.3800 231.7500 1900.0000 ;
      RECT 0.0000 0.6200 1100.0000 1899.3800 ;
      RECT 868.0500 0.0000 1100.0000 0.6200 ;
      RECT 864.0500 0.0000 867.7500 0.6200 ;
      RECT 860.0500 0.0000 863.7500 0.6200 ;
      RECT 856.0500 0.0000 859.7500 0.6200 ;
      RECT 852.0500 0.0000 855.7500 0.6200 ;
      RECT 848.0500 0.0000 851.7500 0.6200 ;
      RECT 844.0500 0.0000 847.7500 0.6200 ;
      RECT 840.0500 0.0000 843.7500 0.6200 ;
      RECT 836.0500 0.0000 839.7500 0.6200 ;
      RECT 832.0500 0.0000 835.7500 0.6200 ;
      RECT 828.0500 0.0000 831.7500 0.6200 ;
      RECT 824.0500 0.0000 827.7500 0.6200 ;
      RECT 820.0500 0.0000 823.7500 0.6200 ;
      RECT 816.0500 0.0000 819.7500 0.6200 ;
      RECT 812.0500 0.0000 815.7500 0.6200 ;
      RECT 808.0500 0.0000 811.7500 0.6200 ;
      RECT 804.0500 0.0000 807.7500 0.6200 ;
      RECT 800.0500 0.0000 803.7500 0.6200 ;
      RECT 796.0500 0.0000 799.7500 0.6200 ;
      RECT 792.0500 0.0000 795.7500 0.6200 ;
      RECT 788.0500 0.0000 791.7500 0.6200 ;
      RECT 784.0500 0.0000 787.7500 0.6200 ;
      RECT 780.0500 0.0000 783.7500 0.6200 ;
      RECT 776.0500 0.0000 779.7500 0.6200 ;
      RECT 772.0500 0.0000 775.7500 0.6200 ;
      RECT 768.0500 0.0000 771.7500 0.6200 ;
      RECT 764.0500 0.0000 767.7500 0.6200 ;
      RECT 760.0500 0.0000 763.7500 0.6200 ;
      RECT 756.0500 0.0000 759.7500 0.6200 ;
      RECT 752.0500 0.0000 755.7500 0.6200 ;
      RECT 748.0500 0.0000 751.7500 0.6200 ;
      RECT 744.0500 0.0000 747.7500 0.6200 ;
      RECT 740.0500 0.0000 743.7500 0.6200 ;
      RECT 736.0500 0.0000 739.7500 0.6200 ;
      RECT 732.0500 0.0000 735.7500 0.6200 ;
      RECT 728.0500 0.0000 731.7500 0.6200 ;
      RECT 724.0500 0.0000 727.7500 0.6200 ;
      RECT 720.0500 0.0000 723.7500 0.6200 ;
      RECT 716.0500 0.0000 719.7500 0.6200 ;
      RECT 712.0500 0.0000 715.7500 0.6200 ;
      RECT 708.0500 0.0000 711.7500 0.6200 ;
      RECT 704.0500 0.0000 707.7500 0.6200 ;
      RECT 700.0500 0.0000 703.7500 0.6200 ;
      RECT 696.0500 0.0000 699.7500 0.6200 ;
      RECT 692.0500 0.0000 695.7500 0.6200 ;
      RECT 688.0500 0.0000 691.7500 0.6200 ;
      RECT 684.0500 0.0000 687.7500 0.6200 ;
      RECT 680.0500 0.0000 683.7500 0.6200 ;
      RECT 676.0500 0.0000 679.7500 0.6200 ;
      RECT 672.0500 0.0000 675.7500 0.6200 ;
      RECT 668.0500 0.0000 671.7500 0.6200 ;
      RECT 664.0500 0.0000 667.7500 0.6200 ;
      RECT 660.0500 0.0000 663.7500 0.6200 ;
      RECT 656.0500 0.0000 659.7500 0.6200 ;
      RECT 652.0500 0.0000 655.7500 0.6200 ;
      RECT 648.0500 0.0000 651.7500 0.6200 ;
      RECT 644.0500 0.0000 647.7500 0.6200 ;
      RECT 640.0500 0.0000 643.7500 0.6200 ;
      RECT 636.0500 0.0000 639.7500 0.6200 ;
      RECT 632.0500 0.0000 635.7500 0.6200 ;
      RECT 628.0500 0.0000 631.7500 0.6200 ;
      RECT 624.0500 0.0000 627.7500 0.6200 ;
      RECT 620.0500 0.0000 623.7500 0.6200 ;
      RECT 616.0500 0.0000 619.7500 0.6200 ;
      RECT 612.0500 0.0000 615.7500 0.6200 ;
      RECT 608.0500 0.0000 611.7500 0.6200 ;
      RECT 604.0500 0.0000 607.7500 0.6200 ;
      RECT 600.0500 0.0000 603.7500 0.6200 ;
      RECT 596.0500 0.0000 599.7500 0.6200 ;
      RECT 592.0500 0.0000 595.7500 0.6200 ;
      RECT 588.0500 0.0000 591.7500 0.6200 ;
      RECT 584.0500 0.0000 587.7500 0.6200 ;
      RECT 580.0500 0.0000 583.7500 0.6200 ;
      RECT 576.0500 0.0000 579.7500 0.6200 ;
      RECT 572.0500 0.0000 575.7500 0.6200 ;
      RECT 568.0500 0.0000 571.7500 0.6200 ;
      RECT 564.0500 0.0000 567.7500 0.6200 ;
      RECT 560.0500 0.0000 563.7500 0.6200 ;
      RECT 556.0500 0.0000 559.7500 0.6200 ;
      RECT 552.0500 0.0000 555.7500 0.6200 ;
      RECT 548.0500 0.0000 551.7500 0.6200 ;
      RECT 544.0500 0.0000 547.7500 0.6200 ;
      RECT 540.0500 0.0000 543.7500 0.6200 ;
      RECT 536.0500 0.0000 539.7500 0.6200 ;
      RECT 532.0500 0.0000 535.7500 0.6200 ;
      RECT 528.0500 0.0000 531.7500 0.6200 ;
      RECT 524.0500 0.0000 527.7500 0.6200 ;
      RECT 520.0500 0.0000 523.7500 0.6200 ;
      RECT 516.0500 0.0000 519.7500 0.6200 ;
      RECT 512.0500 0.0000 515.7500 0.6200 ;
      RECT 508.0500 0.0000 511.7500 0.6200 ;
      RECT 504.0500 0.0000 507.7500 0.6200 ;
      RECT 500.0500 0.0000 503.7500 0.6200 ;
      RECT 496.0500 0.0000 499.7500 0.6200 ;
      RECT 492.0500 0.0000 495.7500 0.6200 ;
      RECT 488.0500 0.0000 491.7500 0.6200 ;
      RECT 484.0500 0.0000 487.7500 0.6200 ;
      RECT 480.0500 0.0000 483.7500 0.6200 ;
      RECT 476.0500 0.0000 479.7500 0.6200 ;
      RECT 472.0500 0.0000 475.7500 0.6200 ;
      RECT 468.0500 0.0000 471.7500 0.6200 ;
      RECT 464.0500 0.0000 467.7500 0.6200 ;
      RECT 460.0500 0.0000 463.7500 0.6200 ;
      RECT 456.0500 0.0000 459.7500 0.6200 ;
      RECT 452.0500 0.0000 455.7500 0.6200 ;
      RECT 448.0500 0.0000 451.7500 0.6200 ;
      RECT 444.0500 0.0000 447.7500 0.6200 ;
      RECT 440.0500 0.0000 443.7500 0.6200 ;
      RECT 436.0500 0.0000 439.7500 0.6200 ;
      RECT 432.0500 0.0000 435.7500 0.6200 ;
      RECT 428.0500 0.0000 431.7500 0.6200 ;
      RECT 424.0500 0.0000 427.7500 0.6200 ;
      RECT 420.0500 0.0000 423.7500 0.6200 ;
      RECT 416.0500 0.0000 419.7500 0.6200 ;
      RECT 412.0500 0.0000 415.7500 0.6200 ;
      RECT 408.0500 0.0000 411.7500 0.6200 ;
      RECT 404.0500 0.0000 407.7500 0.6200 ;
      RECT 400.0500 0.0000 403.7500 0.6200 ;
      RECT 396.0500 0.0000 399.7500 0.6200 ;
      RECT 392.0500 0.0000 395.7500 0.6200 ;
      RECT 388.0500 0.0000 391.7500 0.6200 ;
      RECT 384.0500 0.0000 387.7500 0.6200 ;
      RECT 380.0500 0.0000 383.7500 0.6200 ;
      RECT 376.0500 0.0000 379.7500 0.6200 ;
      RECT 372.0500 0.0000 375.7500 0.6200 ;
      RECT 368.0500 0.0000 371.7500 0.6200 ;
      RECT 364.0500 0.0000 367.7500 0.6200 ;
      RECT 360.0500 0.0000 363.7500 0.6200 ;
      RECT 356.0500 0.0000 359.7500 0.6200 ;
      RECT 352.0500 0.0000 355.7500 0.6200 ;
      RECT 348.0500 0.0000 351.7500 0.6200 ;
      RECT 344.0500 0.0000 347.7500 0.6200 ;
      RECT 340.0500 0.0000 343.7500 0.6200 ;
      RECT 336.0500 0.0000 339.7500 0.6200 ;
      RECT 332.0500 0.0000 335.7500 0.6200 ;
      RECT 328.0500 0.0000 331.7500 0.6200 ;
      RECT 324.0500 0.0000 327.7500 0.6200 ;
      RECT 320.0500 0.0000 323.7500 0.6200 ;
      RECT 316.0500 0.0000 319.7500 0.6200 ;
      RECT 312.0500 0.0000 315.7500 0.6200 ;
      RECT 308.0500 0.0000 311.7500 0.6200 ;
      RECT 304.0500 0.0000 307.7500 0.6200 ;
      RECT 300.0500 0.0000 303.7500 0.6200 ;
      RECT 296.0500 0.0000 299.7500 0.6200 ;
      RECT 292.0500 0.0000 295.7500 0.6200 ;
      RECT 288.0500 0.0000 291.7500 0.6200 ;
      RECT 284.0500 0.0000 287.7500 0.6200 ;
      RECT 280.0500 0.0000 283.7500 0.6200 ;
      RECT 276.0500 0.0000 279.7500 0.6200 ;
      RECT 272.0500 0.0000 275.7500 0.6200 ;
      RECT 268.0500 0.0000 271.7500 0.6200 ;
      RECT 264.0500 0.0000 267.7500 0.6200 ;
      RECT 260.0500 0.0000 263.7500 0.6200 ;
      RECT 256.0500 0.0000 259.7500 0.6200 ;
      RECT 252.0500 0.0000 255.7500 0.6200 ;
      RECT 248.0500 0.0000 251.7500 0.6200 ;
      RECT 244.0500 0.0000 247.7500 0.6200 ;
      RECT 240.0500 0.0000 243.7500 0.6200 ;
      RECT 236.0500 0.0000 239.7500 0.6200 ;
      RECT 232.0500 0.0000 235.7500 0.6200 ;
      RECT 0.0000 0.0000 231.7500 0.6200 ;
    LAYER M5 ;
      RECT 0.0000 0.0000 1100.0000 1900.0000 ;
    LAYER M6 ;
      RECT 0.0000 0.0000 1100.0000 1900.0000 ;
    LAYER M7 ;
      RECT 0.0000 0.0000 1100.0000 1900.0000 ;
    LAYER M8 ;
      RECT 0.0000 0.0000 1100.0000 1900.0000 ;
  END
END fullchip

END LIBRARY
